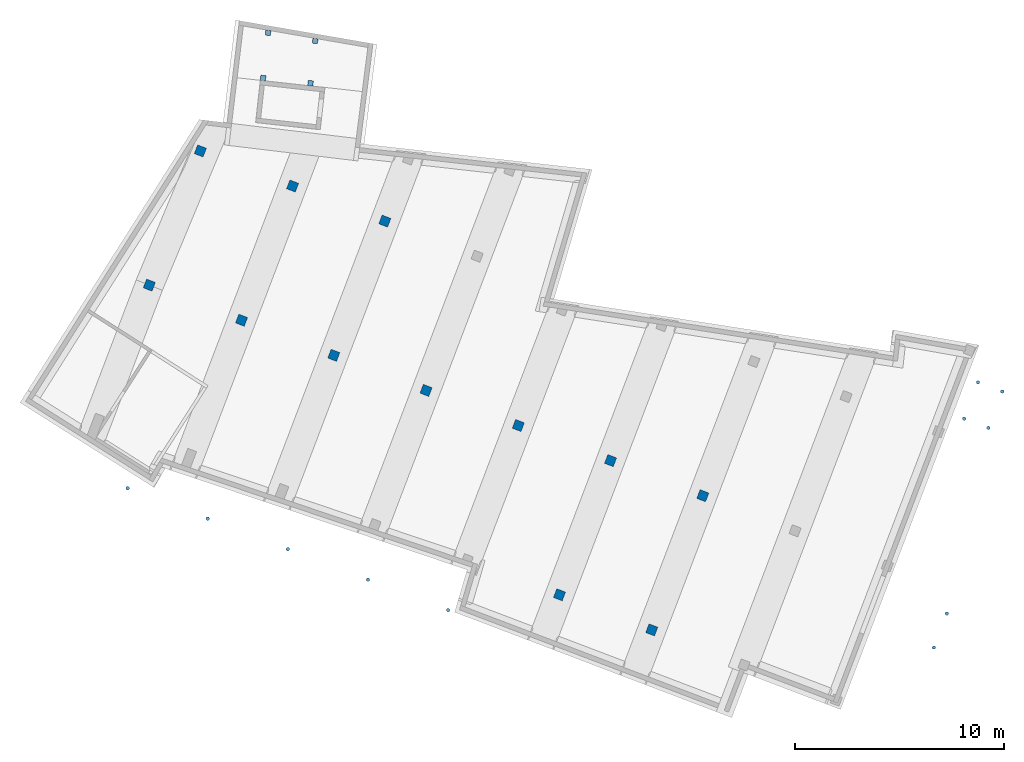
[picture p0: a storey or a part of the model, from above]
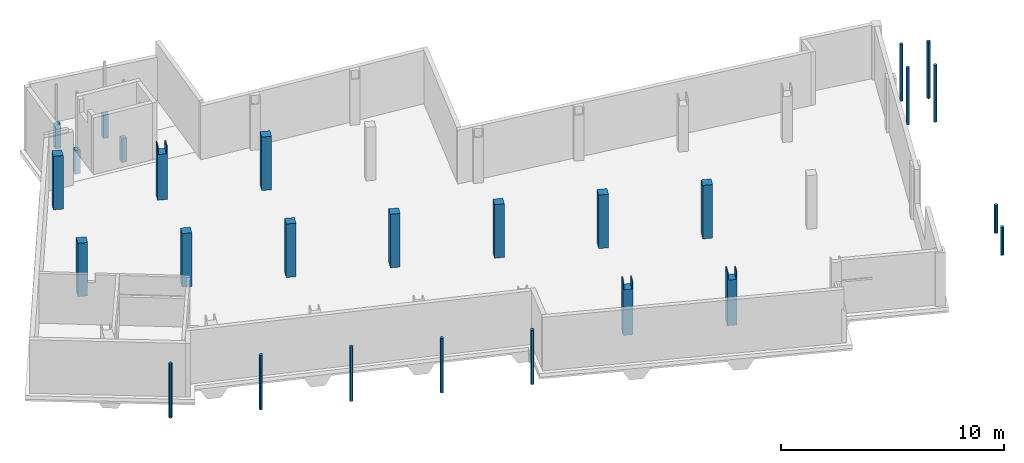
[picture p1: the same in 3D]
Properties of the parts of a building model (IFC2X3), part 1 of 2

# File
Description: ViewDefinition [CoordinationView_V2.0], RevitIdentifiers [ContentGUID: 927a8718-9710-482a-8176-cb94ff4aeceb, VersionGUID: 7923aa44-3987-499f-b0c4-6eacce3661d6, NumberOfSaves: 91], CoordinateReference [CoordinateBase: Shared Coordinates, ProjectSite: Internal], ExchangeRequirement [Structural]
File name: Haarlem - Kruisstraat 30-32_CON_EPA_R25.ifc
Time: 2025-02-14T07:08:31+01:00
Written by: ODA SDAI 24.12
Made in: Autodesk Revit 25.4.0.32 (ENU) - IFC 25.4.0.27

# IfcProject
LongName: Haarlem, Kruisstraat 30-32; Phase: Definitief Ontwerp

# IfcSite, Default
RefLatitude: 42, 24, 53, 508911; RefLongitude: -71, -15, -29, -58837; RefElevation: 0 mm

# IfcBuilding
Pset_BuildingCommon - NumberOfStoreys: 3

# IfcBuildingStorey: Level:Level (3)
Pset_AirSideSystemInformation - sets with these values: 2
Name | LongName = Name | Elevation (mm) | EntranceLevel
-1 kelder | -1 kelder | -3160 | yes
00 begane grond | 00 begane grond | 0 | yes
01 eerste verdieping | 01 eerste verdieping | 4250 | no

# IfcBeam: 130x200mm (11)
In: 00 begane grond
Type - Description: nok 130x200mm; PredefinedType: BEAM
Type - Pset_BeamCommon - LoadBearing: yes
Type - Pset_ConcreteElementGeneral - StructuralClass: -; EnvironmentalClass: -
Type - Pset_FireRatingProperties - FireResistanceRating: -
Type - Pset_ReinforcementBarPitchOfBeam - Description: nok 130x200mm
Classification: 16.12 funderingsconstructies; voeten en balken, fundatie balken (NL-Sfb); Material: beton_gewapend_ihw
Pset_BeamCommon - Slope: 0 deg; IsExternal: no; Reference: nok 130x200mm
Pset_QuantityTakeOff - Reference: nok 130x200mm; sets with these values: 2
ILS Ontwerp en Engineering - 4.3 Dragend: yes; 3.3 Bouwlaag: 00 begane grond; 3.5 Naamgeving element: 16.12_Beton balk; 3.5 Type: nok 130x200mm; 3.6 NL-SfB omschrijving: funderingsconstructies; voeten en balken, fundatie balken; 4.5 C Brandwerendheid hoofddraagconstructie: -; 4.7 Materiaal: beton_gewapend_ihw; 4.8 Bouwfase: Bestaand; 4.8 C Wapeningshoeveelheid: 75,00 kg/m³
Name | Span (mm)
16.12_Beton balk | 3195
16.12_Beton balk | 2267.02
16.12_Beton balk | 2875
2 x 16.12_Beton balk | 580
3 x 16.12_Beton balk | 710
16.12_Beton balk | 6430
16.12_Beton balk | 916.269
16.12_Beton balk | 655

# IfcBeam: 20mm (2)
In: 00 begane grond
Type - Pset_BeamCommon - LoadBearing: yes
Type - Pset_ReinforcementBarPitchOfBeam - Description: w.v.b. ⌀20 S355
Classification: 28.11 hoofddraagconstructies; kolommen en liggers, kolom-/liggerconstructies (NL-Sfb); Material: metaal_staal_profiel_s355
Pset_BeamCommon - IsExternal: no; Reference: 20mm; Span: 7874.2 mm; Slope: 29.1041 deg
Pset_QuantityTakeOff - Reference: 20mm; sets with these values: 2
ILS Ontwerp en Engineering - 4.3 Dragend: yes; 3.3 Bouwlaag: 00 begane grond; 4.7 Materiaal: metaal_staal_profiel_s355; 4.8 Bouwfase: Nieuw
Name (28.11_SF_WVB-StaafRond:20mm:...)
837259
837310

# IfcBeam: 300x300mm, 16.12_Beton balk
In: 00 begane grond
Type - Description: balk 300x600mm; PredefinedType: BEAM; Classification: 16.12 funderingsconstructies; voeten en balken, fundatie balken (NL-Sfb); Material: beton_gewapend_ihw
Type - Pset_BeamCommon - LoadBearing: yes
Type - Pset_ConcreteElementGeneral - StructuralClass: C30/37; EnvironmentalClass: XC3
Type - Pset_FireRatingProperties - FireResistanceRating: -
Type - Pset_ReinforcementBarPitchOfBeam - Description: balk 300x600mm
Pset_BeamCommon - Slope: 0 deg; IsExternal: no; Reference: balk 300x600mm; Span: 14040 mm
Pset_QuantityTakeOff - Reference: balk 300x600mm; sets with these values: 2
ILS Ontwerp en Engineering - 4.3 Dragend: yes; 3.3 Bouwlaag: 00 begane grond; 3.5 Naamgeving element: 16.12_Beton balk; 3.5 Type: balk 300x600mm; 3.6 NL-SfB omschrijving: funderingsconstructies; voeten en balken, fundatie balken; 4.5 C Brandwerendheid hoofddraagconstructie: -; 4.7 Materiaal: beton_gewapend_ihw; 4.8 Bouwfase: Bestaand; 4.8 C Wapeningshoeveelheid: 75,00 kg/m³

# IfcBeam: 300x300mm, 16.12_Beton balk
In: 00 begane grond
Type - Description: balk 300x600mm; PredefinedType: BEAM
Type - Pset_BeamCommon - LoadBearing: yes
Type - Pset_ConcreteElementGeneral - StructuralClass: C30/37; EnvironmentalClass: XC3
Type - Pset_FireRatingProperties - FireResistanceRating: -
Type - Pset_ReinforcementBarPitchOfBeam - Description: balk 300x600mm
Classification: 16.12 funderingsconstructies; voeten en balken, fundatie balken (NL-Sfb); Material: beton_gewapend_ihw
Pset_BeamCommon - Slope: 0 deg; IsExternal: no; Reference: balk 300x600mm; Span: 4451.6 mm
Pset_QuantityTakeOff - Reference: balk 300x600mm; sets with these values: 2
ILS Ontwerp en Engineering - 4.3 Dragend: yes; 3.3 Bouwlaag: 00 begane grond; 3.5 Naamgeving element: 16.12_Beton balk; 3.5 Type: balk 300x600mm; 3.6 NL-SfB omschrijving: funderingsconstructies; voeten en balken, fundatie balken; 4.5 C Brandwerendheid hoofddraagconstructie: -; 4.7 Materiaal: beton_gewapend_ihw; 4.8 Bouwfase: Bestaand; 4.8 C Wapeningshoeveelheid: 75,00 kg/m³

# IfcBeam: 300x400mm (2)
In: 00 begane grond
Type - Description: balk 300x400mm; PredefinedType: BEAM
Type - Pset_BeamCommon - LoadBearing: yes
Type - Pset_ConcreteElementGeneral - StructuralClass: C30/37; EnvironmentalClass: XC3
Type - Pset_FireRatingProperties - FireResistanceRating: -
Type - Pset_ReinforcementBarPitchOfBeam - Description: balk 300x400mm
Classification: 16.12 funderingsconstructies; voeten en balken, fundatie balken (NL-Sfb); Material: beton_gewapend_ihw_c30/37
Pset_BeamCommon - Slope: 0 deg; IsExternal: no; Reference: balk 300x400mm
Pset_QuantityTakeOff - Reference: balk 300x400mm; sets with these values: 2
ILS Ontwerp en Engineering - 4.3 Dragend: yes; 3.3 Bouwlaag: 00 begane grond; 3.5 Naamgeving element: 16.12_Beton balk; 3.5 Type: balk 300x400mm; 3.6 NL-SfB omschrijving: funderingsconstructies; voeten en balken, fundatie balken; 4.5 C Brandwerendheid hoofddraagconstructie: -; 4.7 Materiaal: beton_gewapend_ihw_c30/37; 4.8 Bouwfase: Nieuw; 4.8 C Wapeningshoeveelheid: 75,00 kg/m³
Name | Span (mm)
16.12_Beton balk | 17103.8
16.12_Beton balk | 1206.15

# IfcBeam: 300x400mm (3)
In: 00 begane grond
Type - Description: balk 450x300; PredefinedType: BEAM
Type - Pset_BeamCommon - LoadBearing: yes
Type - Pset_ConcreteElementGeneral - StructuralClass: C30/37; EnvironmentalClass: XC3
Type - Pset_FireRatingProperties - FireResistanceRating: -
Type - Pset_ReinforcementBarPitchOfBeam - Description: balk 450x300
Classification: 16.12 funderingsconstructies; voeten en balken, fundatie balken (NL-Sfb); Material: beton_gewapend_ihw
Pset_BeamCommon - Slope: 0 deg; IsExternal: no; Reference: balk 450x300mm
Pset_QuantityTakeOff - Reference: balk 450x300mm; sets with these values: 2
ILS Ontwerp en Engineering - 4.3 Dragend: yes; 3.3 Bouwlaag: 00 begane grond; 3.5 Naamgeving element: 16.12_Beton balk; 3.5 Type: balk 450x300; 3.6 NL-SfB omschrijving: funderingsconstructies; voeten en balken, fundatie balken; 4.5 C Brandwerendheid hoofddraagconstructie: -; 4.7 Materiaal: beton_gewapend_ihw; 4.8 Bouwfase: Nieuw; 4.8 C Wapeningshoeveelheid: 75,00 kg/m³
Name | Span (mm)
2 x 16.12_Beton balk | 1780
16.12_Beton balk | 1550

# IfcBeam: 650x600mm (11)
In: -1 kelder
Type - Description: versterktestrook; PredefinedType: BEAM; Classification: 16.12 funderingsconstructies; voeten en balken, fundatie balken (NL-Sfb); Material: beton_gewapend_ihw
Type - Pset_BeamCommon - LoadBearing: yes
Type - Pset_ConcreteElementGeneral - StructuralClass: -; EnvironmentalClass: -
Type - Pset_FireRatingProperties - FireResistanceRating: -
Type - Pset_ReinforcementBarPitchOfBeam - Description: versterktestrook
Pset_BeamCommon - Slope: 0 deg; IsExternal: no; Reference: 600x300
Pset_QuantityTakeOff - Reference: 600x300; sets with these values: 2
ILS Ontwerp en Engineering - 4.3 Dragend: yes; 3.3 Bouwlaag: Level : -1 kelder; 3.5 Naamgeving element: 16.12_Beton balk; 3.5 Type: versterktestrook; 3.6 NL-SfB omschrijving: funderingsconstructies; voeten en balken, fundatie balken; 4.5 C Brandwerendheid hoofddraagconstructie: -; 4.7 Materiaal: beton_gewapend_ihw; 4.8 Bouwfase: Bestaand; 4.8 C Wapeningshoeveelheid: 75,00 kg/m³
Name | Span (mm)
16.12_Beton balk | 14210.1
16.12_Beton balk | 2119.67
16.12_Beton balk | 15561.7
16.12_Beton balk | 7614.8
16.12_Beton balk | 1367.46
16.12_Beton balk | 16197.5
16.12_Beton balk | 11143.6
16.12_Beton balk | 6475.45
16.12_Beton balk | 17140
16.12_Beton balk | 4163.4
16.12_Beton balk | 1045.66

# IfcBeam: 650x600mm (17)
Type - Description: versterktestrook; PredefinedType: BEAM
Type - Pset_BeamCommon - LoadBearing: yes
Type - Pset_ConcreteElementGeneral - StructuralClass: -; EnvironmentalClass: -
Type - Pset_FireRatingProperties - FireResistanceRating: -
Type - Pset_ReinforcementBarPitchOfBeam - Description: versterktestrook
Classification: 16.12 funderingsconstructies; voeten en balken, fundatie balken (NL-Sfb); Material: beton_gewapend_ihw
Pset_BeamCommon - Slope: 0 deg; IsExternal: no
Pset_QuantityTakeOff - sets with these values: 2
ILS Ontwerp en Engineering - 4.3 Dragend: yes; 3.5 Naamgeving element: 16.12_Beton balk; 3.5 Type: versterktestrook; 3.6 NL-SfB omschrijving: funderingsconstructies; voeten en balken, fundatie balken; 4.5 C Brandwerendheid hoofddraagconstructie: -; 4.7 Materiaal: beton_gewapend_ihw; 4.8 Bouwfase: Bestaand; 4.8 C Wapeningshoeveelheid: 75,00 kg/m³
Name | In | Pset_BeamCommon, Reference = Pset_QuantityTakeOff, Reference | Span (mm) | 3.3 Bouwlaag
16.12_Beton balk | -1 kelder | 650x600mm | 19480 | -1 kelder
16.12_Beton balk | -1 kelder | 650x600mm | 18460 | -1 kelder
16.12_Beton balk | -1 kelder | 650x600mm | 17031.7 | -1 kelder
16.12_Beton balk | -1 kelder | 650x600mm | 8140 | -1 kelder
16.12_Beton balk | -1 kelder | 650x600mm | 8660 | -1 kelder
16.12_Beton balk | -1 kelder | 650x600mm | 13880 | -1 kelder
16.12_Beton balk | -1 kelder | 650x600mm | 16960 | -1 kelder
16.12_Beton balk | -1 kelder | 650x600mm | 17920 | -1 kelder
16.12_Beton balk | -1 kelder | 650x600mm | 16660 | -1 kelder
16.12_Beton balk | -1 kelder | 700x300 | 18685.9 | -1 kelder
16.12_Beton balk | -1 kelder | 700x300 | 4730 | Level : -1 kelder
16.12_Beton balk | -1 kelder | 700x300 | 2217.02 | Level : -1 kelder
16.12_Beton balk | 00 begane grond | 950x1170mm | 12633.1 | 00 begane grond
16.12_Beton balk | 00 begane grond | 950x1170mm | 738.395 | 00 begane grond
16.12_Beton balk | 00 begane grond | 950x1170mm | 7010.68 | 00 begane grond
16.12_Beton balk | 00 begane grond | 950x1170mm | 6925.56 | 00 begane grond
16.12_Beton balk | 00 begane grond | 950x1170mm | 6964.59 | 00 begane grond

# IfcBeam: DIE10 (22)
In: 01 eerste verdieping
Type - Description: DIE10; PredefinedType: BEAM
Type - Pset_BeamCommon - LoadBearing: yes
Type - Pset_ConcreteElementGeneral - StructuralClass: S235; EnvironmentalClass: -
Type - Pset_FireRatingProperties - FireResistanceRating: 90
Type - Pset_ReinforcementBarPitchOfBeam - Description: DIE10
Classification: 28.11 hoofddraagconstructies; kolommen en liggers, kolom-/liggerconstructies (NL-Sfb); Material: metaal_staal_generiek
Pset_BeamCommon - Slope: 0 deg; IsExternal: no; Reference: DIE10
Pset_QuantityTakeOff - Reference: DIE10; sets with these values: 2
ILS Ontwerp en Engineering - 4.3 Dragend: yes; 3.3 Bouwlaag: 01 eerste verdieping; 3.5 Naamgeving element: 28.11_Stalen balk HEA; 3.5 Type: DIE10; 3.6 NL-SfB omschrijving: hoofddraagconstructies; kolommen en liggers, kolom-/liggerconstructies; 4.5 C Brandwerendheid hoofddraagconstructie: 90; 4.7 Materiaal: metaal_staal_generiek; 4.8 Bouwfase: Bestaand; 4.8 C Sterkteklasse: S235; 4.8 C Milieuklasse: -
Name | Span (mm)
20 x 28.11_Stalen balk HEA | 4730
28.11_Stalen balk HEA | 1205
28.11_Stalen balk HEA | 2179.8

# IfcBeam: DIE16 (2)
In: 01 eerste verdieping
Type - Description: DIE16; PredefinedType: BEAM
Type - Pset_BeamCommon - LoadBearing: yes
Type - Pset_ConcreteElementGeneral - StructuralClass: S235; EnvironmentalClass: -
Type - Pset_FireRatingProperties - FireResistanceRating: 90
Type - Pset_ReinforcementBarPitchOfBeam - Description: DIE16
Classification: 28.11 hoofddraagconstructies; kolommen en liggers, kolom-/liggerconstructies (NL-Sfb); Material: metaal_staal_generiek
Pset_BeamCommon - Slope: 0 deg; IsExternal: no; Reference: DIE16
Pset_QuantityTakeOff - Reference: DIE16; sets with these values: 2
ILS Ontwerp en Engineering - 4.3 Dragend: yes; 3.3 Bouwlaag: 01 eerste verdieping; 3.5 Naamgeving element: 28.11_Stalen balk HEA; 3.5 Type: DIE16; 3.6 NL-SfB omschrijving: hoofddraagconstructies; kolommen en liggers, kolom-/liggerconstructies; 4.5 C Brandwerendheid hoofddraagconstructie: 90; 4.7 Materiaal: metaal_staal_generiek; 4.8 Bouwfase: Bestaand; 4.8 C Sterkteklasse: S235; 4.8 C Milieuklasse: -
Name | Span (mm)
28.11_Stalen balk HEA | 1736.7
28.11_Stalen balk HEA | 4780.1

# IfcBeam: DIE18 (4)
In: 01 eerste verdieping
Type - Description: DIE18; PredefinedType: BEAM
Type - Pset_BeamCommon - LoadBearing: yes
Type - Pset_ConcreteElementGeneral - StructuralClass: S235; EnvironmentalClass: -
Type - Pset_FireRatingProperties - FireResistanceRating: 90
Type - Pset_ReinforcementBarPitchOfBeam - Description: DIE18
Classification: 28.11 hoofddraagconstructies; kolommen en liggers, kolom-/liggerconstructies (NL-Sfb); Material: metaal_staal_generiek
Pset_BeamCommon - Slope: 0 deg; IsExternal: no; Reference: DIE18
Pset_QuantityTakeOff - Reference: DIE18; sets with these values: 2
ILS Ontwerp en Engineering - 4.3 Dragend: yes; 3.3 Bouwlaag: 01 eerste verdieping; 3.5 Naamgeving element: 28.11_Stalen balk HEA; 3.5 Type: DIE18; 3.6 NL-SfB omschrijving: hoofddraagconstructies; kolommen en liggers, kolom-/liggerconstructies; 4.5 C Brandwerendheid hoofddraagconstructie: 90; 4.7 Materiaal: metaal_staal_generiek; 4.8 Bouwfase: Bestaand; 4.8 C Sterkteklasse: S235; 4.8 C Milieuklasse: -
Name | Span (mm)
2 x 28.11_Stalen balk HEA | 2117
28.11_Stalen balk HEA | 2078
28.11_Stalen balk HEA | 3132

# IfcBeam: DIE20, 28.11_Stalen balk HEA
In: 01 eerste verdieping
Type - Description: DIE20; PredefinedType: BEAM
Type - Pset_BeamCommon - LoadBearing: yes
Type - Pset_ConcreteElementGeneral - StructuralClass: S235; EnvironmentalClass: -
Type - Pset_FireRatingProperties - FireResistanceRating: 90
Type - Pset_ReinforcementBarPitchOfBeam - Description: DIE20
Classification: 28.11 hoofddraagconstructies; kolommen en liggers, kolom-/liggerconstructies (NL-Sfb); Material: metaal_staal_generiek
Pset_BeamCommon - Slope: 0 deg; IsExternal: no; Reference: DIE20; Span: 2117 mm
Pset_QuantityTakeOff - Reference: DIE20; sets with these values: 2
ILS Ontwerp en Engineering - 4.3 Dragend: yes; 3.3 Bouwlaag: 01 eerste verdieping; 3.5 Naamgeving element: 28.11_Stalen balk HEA; 3.5 Type: DIE20; 3.6 NL-SfB omschrijving: hoofddraagconstructies; kolommen en liggers, kolom-/liggerconstructies; 4.5 C Brandwerendheid hoofddraagconstructie: 90; 4.7 Materiaal: metaal_staal_generiek; 4.8 Bouwfase: Bestaand; 4.8 C Sterkteklasse: S235; 4.8 C Milieuklasse: -

# IfcBeam: DIE22, 28.11_Stalen balk HEA
In: 01 eerste verdieping
Type - Description: DIE22; PredefinedType: BEAM
Type - Pset_BeamCommon - LoadBearing: yes
Type - Pset_ConcreteElementGeneral - StructuralClass: S235; EnvironmentalClass: -
Type - Pset_FireRatingProperties - FireResistanceRating: 90
Type - Pset_ReinforcementBarPitchOfBeam - Description: DIE22
Classification: 28.11 hoofddraagconstructies; kolommen en liggers, kolom-/liggerconstructies (NL-Sfb); Material: metaal_staal_generiek
Pset_BeamCommon - Slope: 0 deg; IsExternal: no; Reference: DIE22; Span: 3227.6 mm
Pset_QuantityTakeOff - Reference: DIE22; sets with these values: 2
ILS Ontwerp en Engineering - 4.3 Dragend: yes; 3.3 Bouwlaag: 01 eerste verdieping; 3.5 Naamgeving element: 28.11_Stalen balk HEA; 3.5 Type: DIE22; 3.6 NL-SfB omschrijving: hoofddraagconstructies; kolommen en liggers, kolom-/liggerconstructies; 4.5 C Brandwerendheid hoofddraagconstructie: 90; 4.7 Materiaal: metaal_staal_generiek; 4.8 Bouwfase: Bestaand; 4.8 C Sterkteklasse: S235; 4.8 C Milieuklasse: -

# IfcBeam: DIE24 (2)
In: 01 eerste verdieping
Type - Description: DIE24; PredefinedType: BEAM
Type - Pset_BeamCommon - LoadBearing: yes
Type - Pset_ConcreteElementGeneral - StructuralClass: S235; EnvironmentalClass: -
Type - Pset_FireRatingProperties - FireResistanceRating: 90
Type - Pset_ReinforcementBarPitchOfBeam - Description: DIE24
Classification: 28.11 hoofddraagconstructies; kolommen en liggers, kolom-/liggerconstructies (NL-Sfb); Material: metaal_staal_generiek
Pset_BeamCommon - Slope: 0 deg; IsExternal: no; Span: 4730 mm; Reference: DIE24
Pset_QuantityTakeOff - Reference: DIE24; sets with these values: 2
ILS Ontwerp en Engineering - 4.3 Dragend: yes; 3.3 Bouwlaag: 01 eerste verdieping; 3.5 Naamgeving element: 28.11_Stalen balk HEA; 3.5 Type: DIE24; 3.6 NL-SfB omschrijving: hoofddraagconstructies; kolommen en liggers, kolom-/liggerconstructies; 4.5 C Brandwerendheid hoofddraagconstructie: 90; 4.7 Materiaal: metaal_staal_generiek; 4.8 Bouwfase: Bestaand; 4.8 C Sterkteklasse: S235; 4.8 C Milieuklasse: -

# IfcBeam: DIE26 (10)
In: 01 eerste verdieping
Type - Description: DIE26; PredefinedType: BEAM
Type - Pset_BeamCommon - LoadBearing: yes
Type - Pset_ConcreteElementGeneral - StructuralClass: S235; EnvironmentalClass: -
Type - Pset_FireRatingProperties - FireResistanceRating: 90
Type - Pset_ReinforcementBarPitchOfBeam - Description: DIE26
Classification: 28.11 hoofddraagconstructies; kolommen en liggers, kolom-/liggerconstructies (NL-Sfb); Material: metaal_staal_generiek
Pset_BeamCommon - Slope: 0 deg; IsExternal: no; Reference: DIE26
Pset_QuantityTakeOff - Reference: DIE26; sets with these values: 2
ILS Ontwerp en Engineering - 4.3 Dragend: yes; 3.3 Bouwlaag: 01 eerste verdieping; 3.5 Naamgeving element: 28.11_Stalen balk HEA; 3.5 Type: DIE26; 3.6 NL-SfB omschrijving: hoofddraagconstructies; kolommen en liggers, kolom-/liggerconstructies; 4.5 C Brandwerendheid hoofddraagconstructie: 90; 4.7 Materiaal: metaal_staal_generiek; 4.8 Bouwfase: Bestaand; 4.8 C Sterkteklasse: S235; 4.8 C Milieuklasse: -
Name | Span (mm)
28.11_Stalen balk HEA | 4730
28.11_Stalen balk HEA | 4479.3
28.11_Stalen balk HEA | 4317
28.11_Stalen balk HEA | 4449.2
28.11_Stalen balk HEA | 6880
28.11_Stalen balk HEA | 6789
28.11_Stalen balk HEA | 1799.2
28.11_Stalen balk HEA | 5010.3
28.11_Stalen balk HEA | 6900
28.11_Stalen balk HEA | 4220

# IfcBeam: DIE28 (2)
In: 01 eerste verdieping
Type - Description: DIE28; PredefinedType: BEAM
Type - Pset_BeamCommon - LoadBearing: yes
Type - Pset_ConcreteElementGeneral - StructuralClass: S235; EnvironmentalClass: -
Type - Pset_FireRatingProperties - FireResistanceRating: 90
Type - Pset_ReinforcementBarPitchOfBeam - Description: DIE28
Classification: 28.11 hoofddraagconstructies; kolommen en liggers, kolom-/liggerconstructies (NL-Sfb); Material: metaal_staal_generiek
Pset_BeamCommon - Slope: 0 deg; IsExternal: no; Reference: DIE28
Pset_QuantityTakeOff - Reference: DIE28; sets with these values: 2
ILS Ontwerp en Engineering - 4.3 Dragend: yes; 3.3 Bouwlaag: 01 eerste verdieping; 3.5 Naamgeving element: 28.11_Stalen balk HEA; 3.5 Type: DIE28; 3.6 NL-SfB omschrijving: hoofddraagconstructies; kolommen en liggers, kolom-/liggerconstructies; 4.5 C Brandwerendheid hoofddraagconstructie: 90; 4.7 Materiaal: metaal_staal_generiek; 4.8 Bouwfase: Bestaand; 4.8 C Sterkteklasse: S235; 4.8 C Milieuklasse: -
Name | Span (mm)
28.11_Stalen balk HEA | 4730.1
28.11_Stalen balk HEA | 4203.6

# IfcBeam: DIE32, 28.11_Stalen balk HEA
In: 01 eerste verdieping
Type - Description: DIE32; PredefinedType: BEAM
Type - Pset_BeamCommon - LoadBearing: yes
Type - Pset_ConcreteElementGeneral - StructuralClass: S235; EnvironmentalClass: -
Type - Pset_FireRatingProperties - FireResistanceRating: 90
Type - Pset_ReinforcementBarPitchOfBeam - Description: DIE32
Classification: 28.11 hoofddraagconstructies; kolommen en liggers, kolom-/liggerconstructies (NL-Sfb); Material: metaal_staal_generiek
Pset_BeamCommon - Slope: 0 deg; IsExternal: no; Reference: DIE32; Span: 5066.4 mm
Pset_QuantityTakeOff - Reference: DIE32; sets with these values: 2
ILS Ontwerp en Engineering - 4.3 Dragend: yes; 3.3 Bouwlaag: 01 eerste verdieping; 3.5 Naamgeving element: 28.11_Stalen balk HEA; 3.5 Type: DIE32; 3.6 NL-SfB omschrijving: hoofddraagconstructies; kolommen en liggers, kolom-/liggerconstructies; 4.5 C Brandwerendheid hoofddraagconstructie: 90; 4.7 Materiaal: metaal_staal_generiek; 4.8 Bouwfase: Bestaand; 4.8 C Sterkteklasse: S235; 4.8 C Milieuklasse: -

# IfcBeam: DIE34, 28.11_Stalen balk HEA
In: 01 eerste verdieping
Type - Description: DIE34; PredefinedType: BEAM
Type - Pset_BeamCommon - LoadBearing: yes
Type - Pset_ConcreteElementGeneral - StructuralClass: S235; EnvironmentalClass: -
Type - Pset_FireRatingProperties - FireResistanceRating: 90
Type - Pset_ReinforcementBarPitchOfBeam - Description: DIE34
Classification: 28.11 hoofddraagconstructies; kolommen en liggers, kolom-/liggerconstructies (NL-Sfb); Material: metaal_staal_generiek
Pset_BeamCommon - Slope: 0 deg; IsExternal: no; Reference: DIE34; Span: 5970 mm
Pset_QuantityTakeOff - Reference: DIE34; sets with these values: 2
ILS Ontwerp en Engineering - 4.3 Dragend: yes; 3.3 Bouwlaag: 01 eerste verdieping; 3.5 Naamgeving element: 28.11_Stalen balk HEA; 3.5 Type: DIE34; 3.6 NL-SfB omschrijving: hoofddraagconstructies; kolommen en liggers, kolom-/liggerconstructies; 4.5 C Brandwerendheid hoofddraagconstructie: 90; 4.7 Materiaal: metaal_staal_generiek; 4.8 Bouwfase: Bestaand; 4.8 C Sterkteklasse: S235; 4.8 C Milieuklasse: -

# IfcBeam: DIE38 (11)
In: 01 eerste verdieping
Type - Description: DIE38; PredefinedType: BEAM
Type - Pset_BeamCommon - LoadBearing: yes
Type - Pset_ConcreteElementGeneral - StructuralClass: S235; EnvironmentalClass: -
Type - Pset_FireRatingProperties - FireResistanceRating: 90
Type - Pset_ReinforcementBarPitchOfBeam - Description: DIE38
Classification: 28.11 hoofddraagconstructies; kolommen en liggers, kolom-/liggerconstructies (NL-Sfb); Material: metaal_staal_generiek
Pset_BeamCommon - Slope: 0 deg; IsExternal: no; Reference: DIE38
Pset_QuantityTakeOff - Reference: DIE38; sets with these values: 2
ILS Ontwerp en Engineering - 4.3 Dragend: yes; 3.3 Bouwlaag: 01 eerste verdieping; 3.5 Naamgeving element: 28.11_Stalen balk HEA; 3.5 Type: DIE38; 3.6 NL-SfB omschrijving: hoofddraagconstructies; kolommen en liggers, kolom-/liggerconstructies; 4.5 C Brandwerendheid hoofddraagconstructie: 90; 4.7 Materiaal: metaal_staal_generiek; 4.8 Bouwfase: Bestaand; 4.8 C Sterkteklasse: S235; 4.8 C Milieuklasse: -
Name | Span (mm)
28.11_Stalen balk HEA | 265
4 x 28.11_Stalen balk HEA | 13760
28.11_Stalen balk HEA | 12859.2
28.11_Stalen balk HEA | 14027.2
28.11_Stalen balk HEA | 14169.1
28.11_Stalen balk HEA | 14356.4
28.11_Stalen balk HEA | 14647.7
28.11_Stalen balk HEA | 7005

# IfcBeam: HEA140 (3)
In: 00 begane grond
Type - Description: HEA140; PredefinedType: BEAM
Type - Pset_BeamCommon - LoadBearing: yes
Type - Pset_ConcreteElementGeneral - StructuralClass: S235; EnvironmentalClass: -
Type - Pset_FireRatingProperties - FireResistanceRating: 90
Type - Pset_ReinforcementBarPitchOfBeam - Description: HEA140
Classification: 28.11 hoofddraagconstructies; kolommen en liggers, kolom-/liggerconstructies (NL-Sfb); Material: metaal_staal_generiek
Pset_BeamCommon - IsExternal: no; Reference: HEA140
Pset_QuantityTakeOff - Reference: HEA140; sets with these values: 2
ILS Ontwerp en Engineering - 4.3 Dragend: yes; 3.3 Bouwlaag: 00 begane grond; 3.5 Naamgeving element: 28.11_Stalen balk HEA; 3.5 Type: HEA140; 3.6 NL-SfB omschrijving: hoofddraagconstructies; kolommen en liggers, kolom-/liggerconstructies; 4.5 C Brandwerendheid hoofddraagconstructie: 90; 4.7 Materiaal: metaal_staal_generiek; 4.8 Bouwfase: Nieuw; 4.8 C Sterkteklasse: S235; 4.8 C Milieuklasse: -
Name | Slope (deg) | Span (mm)
28.11_Stalen balk HEA | 0 | 2140
28.11_Stalen balk HEA | 0 | 2280.5
28.11_Stalen balk HEA | 16.9275 | 2404.2

# IfcBeam: HEA160 (16)
Type - Description: HEA160; PredefinedType: BEAM
Type - Pset_BeamCommon - LoadBearing: yes
Type - Pset_ConcreteElementGeneral - StructuralClass: S235; EnvironmentalClass: -
Type - Pset_FireRatingProperties - FireResistanceRating: 90
Type - Pset_ReinforcementBarPitchOfBeam - Description: HEA160
Classification: 28.11 hoofddraagconstructies; kolommen en liggers, kolom-/liggerconstructies (NL-Sfb)
Pset_BeamCommon - Slope: 0 deg; IsExternal: no; Reference: HEA160
Pset_QuantityTakeOff - Reference: HEA160; sets with these values: 2
ILS Ontwerp en Engineering - 4.3 Dragend: yes; 3.5 Naamgeving element: 28.11_Stalen balk HEA; 3.5 Type: HEA160; 3.6 NL-SfB omschrijving: hoofddraagconstructies; kolommen en liggers, kolom-/liggerconstructies; 4.5 C Brandwerendheid hoofddraagconstructie: 90; 4.8 Bouwfase: Nieuw; 4.8 C Sterkteklasse: S235; 4.8 C Milieuklasse: -
Name | In | Material = 4.7 Materiaal | Span (mm) | 3.3 Bouwlaag
28.11_Stalen balk HEA | 01 eerste verdieping | metaal_staal_profiel_s235 | 4730 | 01 eerste verdieping
28.11_Stalen balk HEA | 01 eerste verdieping | metaal_staal_profiel_s235 | 4835.6 | 01 eerste verdieping
28.11_Stalen balk HEA | 01 eerste verdieping | metaal_staal_profiel_s235 | 1706.7 | 01 eerste verdieping
28.11_Stalen balk HEA | 00 begane grond | metaal_staal_generiek | 5417.6 | 00 begane grond
28.11_Stalen balk HEA | 00 begane grond | metaal_staal_generiek | 904.8 | 00 begane grond
28.11_Stalen balk HEA | 00 begane grond | metaal_staal_generiek | 422.7 | 00 begane grond
2 x 28.11_Stalen balk HEA | 01 eerste verdieping | metaal_staal_profiel_s235 | 4835.7 | 01 eerste verdieping
2 x 28.11_Stalen balk HEA | 01 eerste verdieping | metaal_staal_profiel_s235 | 3550 | 01 eerste verdieping
5 x 28.11_Stalen balk HEA | 01 eerste verdieping | metaal_staal_profiel_s235 | 3700 | 01 eerste verdieping
28.11_Stalen balk HEA | 01 eerste verdieping | metaal_staal_profiel_s235 | 2447 | 01 eerste verdieping

# IfcBeam: HEA180 (15)
In: 01 eerste verdieping
Type - Description: HEA180; PredefinedType: BEAM
Type - Pset_BeamCommon - LoadBearing: yes
Type - Pset_ConcreteElementGeneral - StructuralClass: S235; EnvironmentalClass: -
Type - Pset_FireRatingProperties - FireResistanceRating: 90
Type - Pset_ReinforcementBarPitchOfBeam - Description: HEA180
Classification: 28.11 hoofddraagconstructies; kolommen en liggers, kolom-/liggerconstructies (NL-Sfb)
Pset_BeamCommon - IsExternal: no; Reference: HEA180
Pset_QuantityTakeOff - Reference: HEA180; sets with these values: 2
ILS Ontwerp en Engineering - 4.3 Dragend: yes; 3.3 Bouwlaag: 01 eerste verdieping; 3.5 Naamgeving element: 28.11_Stalen balk HEA; 3.5 Type: HEA180; 3.6 NL-SfB omschrijving: hoofddraagconstructies; kolommen en liggers, kolom-/liggerconstructies; 4.5 C Brandwerendheid hoofddraagconstructie: 90; 4.8 Bouwfase: Nieuw; 4.8 C Sterkteklasse: S235; 4.8 C Milieuklasse: -
Name | Material = 4.7 Materiaal | Slope (deg) | Span (mm)
28.11_Stalen balk HEA | metaal_staal_profiel_s235 | 0 | 3550
2 x 28.11_Stalen balk HEA | metaal_staal_profiel_s235 | 0 | 4730
28.11_Stalen balk HEA | metaal_staal_generiek | 0.000338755 | 4730
28.11_Stalen balk HEA | metaal_staal_generiek | 0.000338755 | 2356.7
2 x 28.11_Stalen balk HEA | metaal_staal_generiek | 0 | 4730
28.11_Stalen balk HEA | metaal_staal_generiek | 0 | 2330
28.11_Stalen balk HEA | metaal_staal_generiek | 0 | 3272.8
28.11_Stalen balk HEA | metaal_staal_generiek | 0 | 4729.9
28.11_Stalen balk HEA | metaal_staal_generiek | 0 | 1620
28.11_Stalen balk HEA | metaal_staal_profiel_s235 | 0 | 2330
28.11_Stalen balk HEA | metaal_staal_profiel_s235 | 0 | 3188.5
28.11_Stalen balk HEA | metaal_staal_profiel_s235 | 0 | 2234.8
28.11_Stalen balk HEA | metaal_staal_profiel_s235 | 0 | 1234.9

# IfcBeam: HEA200 (13)
Type - Description: HEA200; PredefinedType: BEAM
Type - Pset_BeamCommon - LoadBearing: yes
Type - Pset_ConcreteElementGeneral - StructuralClass: S235; EnvironmentalClass: -
Type - Pset_FireRatingProperties - FireResistanceRating: 90
Type - Pset_ReinforcementBarPitchOfBeam - Description: HEA200
Classification: 28.11 hoofddraagconstructies; kolommen en liggers, kolom-/liggerconstructies (NL-Sfb); Material: metaal_staal_profiel_s235
Pset_BeamCommon - Slope: 0 deg; IsExternal: no; Reference: HEA200
Pset_QuantityTakeOff - Reference: HEA200; sets with these values: 2
ILS Ontwerp en Engineering - 4.3 Dragend: yes; 3.5 Naamgeving element: 28.11_Stalen balk HEA; 3.5 Type: HEA200; 3.6 NL-SfB omschrijving: hoofddraagconstructies; kolommen en liggers, kolom-/liggerconstructies; 4.5 C Brandwerendheid hoofddraagconstructie: 90; 4.7 Materiaal: metaal_staal_profiel_s235; 4.8 Bouwfase: Nieuw; 4.8 C Sterkteklasse: S235; 4.8 C Milieuklasse: -
Name | In | Span (mm) | 3.3 Bouwlaag
10 x 28.11_Stalen balk HEA | 01 eerste verdieping | 3700 | 01 eerste verdieping
28.11_Stalen balk HEA | 01 eerste verdieping | 3469.4 | 01 eerste verdieping
28.11_Stalen balk HEA | 00 begane grond | 7324.1 | 00 begane grond
28.11_Stalen balk HEA | 01 eerste verdieping | 2088.3 | 01 eerste verdieping

# IfcBeam: HEA220 (6)
Type - Description: HEA220; PredefinedType: BEAM
Type - Pset_BeamCommon - LoadBearing: yes
Type - Pset_ConcreteElementGeneral - StructuralClass: S235; EnvironmentalClass: -
Type - Pset_FireRatingProperties - FireResistanceRating: 90
Type - Pset_ReinforcementBarPitchOfBeam - Description: HEA220
Classification: 28.11 hoofddraagconstructies; kolommen en liggers, kolom-/liggerconstructies (NL-Sfb)
Pset_BeamCommon - Slope: 0 deg; IsExternal: no; Reference: HEA220
Pset_QuantityTakeOff - Reference: HEA220; sets with these values: 2
ILS Ontwerp en Engineering - 4.3 Dragend: yes; 3.5 Naamgeving element: 28.11_Stalen balk HEA; 3.5 Type: HEA220; 3.6 NL-SfB omschrijving: hoofddraagconstructies; kolommen en liggers, kolom-/liggerconstructies; 4.5 C Brandwerendheid hoofddraagconstructie: 90; 4.8 Bouwfase: Nieuw; 4.8 C Sterkteklasse: S235; 4.8 C Milieuklasse: -
Name | In | Material = 4.7 Materiaal | Span (mm) | 3.3 Bouwlaag
28.11_Stalen balk HEA | 00 begane grond | metaal_staal_generiek | 4886.4 | 00 begane grond
2 x 28.11_Stalen balk HEA | 01 eerste verdieping | metaal_staal_profiel_s235 | 3550 | 01 eerste verdieping
2 x 28.11_Stalen balk HEA | 01 eerste verdieping | metaal_staal_profiel_s235 | 1234.9 | 01 eerste verdieping
28.11_Stalen balk HEA | 00 begane grond | metaal_staal_generiek | 4730 | 00 begane grond

# IfcBeam: HEA260 (7)
In: 01 eerste verdieping
Type - Description: HEA260; PredefinedType: BEAM
Type - Pset_BeamCommon - LoadBearing: yes
Type - Pset_ConcreteElementGeneral - StructuralClass: S235; EnvironmentalClass: -
Type - Pset_FireRatingProperties - FireResistanceRating: 90
Type - Pset_ReinforcementBarPitchOfBeam - Description: HEA260
Classification: 28.11 hoofddraagconstructies; kolommen en liggers, kolom-/liggerconstructies (NL-Sfb); Material: metaal_staal_profiel_s235
Pset_BeamCommon - Slope: 0 deg; IsExternal: no; Reference: HEA260
Pset_QuantityTakeOff - Reference: HEA260; sets with these values: 2
ILS Ontwerp en Engineering - 4.3 Dragend: yes; 3.3 Bouwlaag: 01 eerste verdieping; 3.5 Naamgeving element: 28.11_Stalen balk HEA; 3.5 Type: HEA260; 3.6 NL-SfB omschrijving: hoofddraagconstructies; kolommen en liggers, kolom-/liggerconstructies; 4.5 C Brandwerendheid hoofddraagconstructie: 90; 4.7 Materiaal: metaal_staal_profiel_s235; 4.8 Bouwfase: Nieuw; 4.8 C Sterkteklasse: S235; 4.8 C Milieuklasse: -
Name | Span (mm)
28.11_Stalen balk HEA | 5854.5
28.11_Stalen balk HEA | 5671.5
28.11_Stalen balk HEA | 4648.3
28.11_Stalen balk HEA | 3700
28.11_Stalen balk HEA | 6961.4
28.11_Stalen balk HEA | 6427.1
28.11_Stalen balk HEA | 4387.8

# IfcBeam: HEA300 (40)
In: 01 eerste verdieping
Type - Description: HEA300; PredefinedType: BEAM
Type - Pset_BeamCommon - LoadBearing: yes
Type - Pset_ConcreteElementGeneral - StructuralClass: S235; EnvironmentalClass: -
Type - Pset_FireRatingProperties - FireResistanceRating: 90
Type - Pset_ReinforcementBarPitchOfBeam - Description: HEA300
Classification: 28.11 hoofddraagconstructies; kolommen en liggers, kolom-/liggerconstructies (NL-Sfb); Material: metaal_staal_profiel_s235
Pset_BeamCommon - Slope: 0 deg; IsExternal: no; Reference: HEA300
Pset_QuantityTakeOff - Reference: HEA300; sets with these values: 2
ILS Ontwerp en Engineering - 4.3 Dragend: yes; 3.3 Bouwlaag: 01 eerste verdieping; 3.5 Naamgeving element: 28.11_Stalen balk HEA; 3.5 Type: HEA300; 3.6 NL-SfB omschrijving: hoofddraagconstructies; kolommen en liggers, kolom-/liggerconstructies; 4.5 C Brandwerendheid hoofddraagconstructie: 90; 4.7 Materiaal: metaal_staal_profiel_s235; 4.8 Bouwfase: Nieuw; 4.8 C Sterkteklasse: S235; 4.8 C Milieuklasse: -
Name | Span (mm)
2 x 28.11_Stalen balk HEA | 4236.2
24 x 28.11_Stalen balk HEA | 4730
3 x 28.11_Stalen balk HEA | 4479.3
28.11_Stalen balk HEA | 4224.3
4 x 28.11_Stalen balk HEA | 3700
2 x 28.11_Stalen balk HEA | 3550
2 x 28.11_Stalen balk HEA | 4742.4
28.11_Stalen balk HEA | 4815.5
28.11_Stalen balk HEA | 4273

# IfcBeam: HEA320 (16)
In: 01 eerste verdieping
Type - Description: HEA320; PredefinedType: BEAM
Type - Pset_BeamCommon - LoadBearing: yes
Type - Pset_ConcreteElementGeneral - StructuralClass: S235; EnvironmentalClass: -
Type - Pset_FireRatingProperties - FireResistanceRating: 90
Type - Pset_ReinforcementBarPitchOfBeam - Description: HEA320
Classification: 28.11 hoofddraagconstructies; kolommen en liggers, kolom-/liggerconstructies (NL-Sfb)
Pset_BeamCommon - Slope: 0 deg; IsExternal: no; Reference: HEA320
Pset_QuantityTakeOff - Reference: HEA320; sets with these values: 2
ILS Ontwerp en Engineering - 4.3 Dragend: yes; 3.3 Bouwlaag: 01 eerste verdieping; 3.5 Naamgeving element: 28.11_Stalen balk HEA; 3.5 Type: HEA320; 3.6 NL-SfB omschrijving: hoofddraagconstructies; kolommen en liggers, kolom-/liggerconstructies; 4.5 C Brandwerendheid hoofddraagconstructie: 90; 4.8 Bouwfase: Nieuw; 4.8 C Sterkteklasse: S235; 4.8 C Milieuklasse: -
Name | Material = 4.7 Materiaal | Span (mm)
28.11_Stalen balk HEA | metaal_staal_profiel_s235 | 6507.5
28.11_Stalen balk HEA | metaal_staal_profiel_s235 | 6826.1
28.11_Stalen balk HEA | metaal_staal_profiel_s235 | 7785.4
28.11_Stalen balk HEA | metaal_staal_profiel_s235 | 6961.3
28.11_Stalen balk HEA | metaal_staal_profiel_s235 | 6963
28.11_Stalen balk HEA | metaal_staal_profiel_s235 | 3700.1
28.11_Stalen balk HEA | metaal_staal_profiel_s235 | 7848.4
28.11_Stalen balk HEA | metaal_staal_profiel_s235 | 4668.9
28.11_Stalen balk HEA | metaal_staal_profiel_s235 | 1456.1
28.11_Stalen balk HEA | metaal_staal_profiel_s235 | 2862
28.11_Stalen balk HEA | metaal_staal_profiel_s235 | 8216.7
28.11_Stalen balk HEA | metaal_staal_profiel_s235 | 13479.2
28.11_Stalen balk HEA | metaal_staal_profiel_s235 | 5378.8
28.11_Stalen balk HEA | metaal_staal_profiel_s235 | 6250.2
28.11_Stalen balk HEA | metaal_staal_profiel_s235 | 7492.5
28.11_Stalen balk HEA | metaal_staal_generiek | 4709.9

# IfcBeam: HEA400 (2)
In: 01 eerste verdieping
Type - Description: HEA400; PredefinedType: BEAM
Type - Pset_BeamCommon - LoadBearing: yes
Type - Pset_ConcreteElementGeneral - StructuralClass: S235; EnvironmentalClass: -
Type - Pset_FireRatingProperties - FireResistanceRating: 90
Type - Pset_ReinforcementBarPitchOfBeam - Description: HEA400
Classification: 28.11 hoofddraagconstructies; kolommen en liggers, kolom-/liggerconstructies (NL-Sfb); Material: metaal_staal_generiek
Pset_BeamCommon - Slope: 0 deg; IsExternal: no
Pset_QuantityTakeOff - sets with these values: 2
ILS Ontwerp en Engineering - 4.3 Dragend: yes; 3.3 Bouwlaag: 01 eerste verdieping; 3.5 Naamgeving element: 28.11_Stalen balk HEA; 3.5 Type: HEA400; 3.6 NL-SfB omschrijving: hoofddraagconstructies; kolommen en liggers, kolom-/liggerconstructies; 4.5 C Brandwerendheid hoofddraagconstructie: 90; 4.7 Materiaal: metaal_staal_generiek; 4.8 C Sterkteklasse: S235; 4.8 C Milieuklasse: -
Name | Pset_BeamCommon, Reference = Pset_QuantityTakeOff, Reference | Span (mm) | 4.8 Bouwfase
28.11_Stalen balk HEA | DIE40 | 14365 | Bestaand
28.11_Stalen balk HEA | HEA400 | 7005 | Nieuw

# IfcBeam: HEA550, 28.11_Stalen balk HEA
In: 01 eerste verdieping
Type - Description: HEA550; PredefinedType: BEAM
Type - Pset_BeamCommon - LoadBearing: yes
Type - Pset_ConcreteElementGeneral - StructuralClass: S235; EnvironmentalClass: -
Type - Pset_FireRatingProperties - FireResistanceRating: 90
Type - Pset_ReinforcementBarPitchOfBeam - Description: HEA550
Classification: 28.11 hoofddraagconstructies; kolommen en liggers, kolom-/liggerconstructies (NL-Sfb); Material: metaal_staal_generiek
Pset_BeamCommon - Slope: 0 deg; IsExternal: no; Reference: DIE55; Span: 7293.5 mm
Pset_QuantityTakeOff - Reference: DIE55; sets with these values: 2
ILS Ontwerp en Engineering - 4.3 Dragend: yes; 3.3 Bouwlaag: 01 eerste verdieping; 3.5 Naamgeving element: 28.11_Stalen balk HEA; 3.5 Type: HEA550; 3.6 NL-SfB omschrijving: hoofddraagconstructies; kolommen en liggers, kolom-/liggerconstructies; 4.5 C Brandwerendheid hoofddraagconstructie: 90; 4.7 Materiaal: metaal_staal_generiek; 4.8 Bouwfase: Bestaand; 4.8 C Sterkteklasse: S235; 4.8 C Milieuklasse: -

# IfcBeam: HEB120 (5)
In: 00 begane grond
Type - Description: HEB120; PredefinedType: BEAM
Type - Pset_BeamCommon - LoadBearing: yes
Type - Pset_ConcreteElementGeneral - StructuralClass: S235; EnvironmentalClass: -
Type - Pset_FireRatingProperties - FireResistanceRating: 90
Type - Pset_ReinforcementBarPitchOfBeam - Description: HEB120
Classification: 28.11 hoofddraagconstructies; kolommen en liggers, kolom-/liggerconstructies (NL-Sfb); Material: metaal_staal_generiek
Pset_BeamCommon - Slope: 0 deg; IsExternal: no; Reference: HEB120
Pset_QuantityTakeOff - Reference: HEB120; sets with these values: 2
ILS Ontwerp en Engineering - 4.3 Dragend: yes; 3.3 Bouwlaag: 00 begane grond; 3.5 Naamgeving element: 28.11_Stalen balk HEB; 3.5 Type: HEB120; 3.6 NL-SfB omschrijving: hoofddraagconstructies; kolommen en liggers, kolom-/liggerconstructies; 4.5 C Brandwerendheid hoofddraagconstructie: 90; 4.7 Materiaal: metaal_staal_generiek; 4.8 Bouwfase: Nieuw; 4.8 C Sterkteklasse: S235; 4.8 C Milieuklasse: -
Name | Span (mm)
28.11_Stalen balk HEB | 1275
2 x 28.11_Stalen balk HEB | 2857.5
2 x 28.11_Stalen balk HEB | 3170

# IfcBeam: HEB320 (9)
In: 01 eerste verdieping
Type - Description: HEB320; PredefinedType: BEAM
Type - Pset_BeamCommon - LoadBearing: yes
Type - Pset_ConcreteElementGeneral - StructuralClass: S235; EnvironmentalClass: -
Type - Pset_FireRatingProperties - FireResistanceRating: 90
Type - Pset_ReinforcementBarPitchOfBeam - Description: HEB320
Classification: 28.11 hoofddraagconstructies; kolommen en liggers, kolom-/liggerconstructies (NL-Sfb); Material: metaal_staal_profiel_s235
Pset_BeamCommon - Slope: 0 deg; IsExternal: no; Reference: HEB320
Pset_QuantityTakeOff - Reference: HEB320; sets with these values: 2
ILS Ontwerp en Engineering - 4.3 Dragend: yes; 3.3 Bouwlaag: 01 eerste verdieping; 3.5 Naamgeving element: 28.11_Stalen balk HEB; 3.5 Type: HEB320; 3.6 NL-SfB omschrijving: hoofddraagconstructies; kolommen en liggers, kolom-/liggerconstructies; 4.5 C Brandwerendheid hoofddraagconstructie: 90; 4.7 Materiaal: metaal_staal_profiel_s235; 4.8 Bouwfase: Nieuw; 4.8 C Sterkteklasse: S235; 4.8 C Milieuklasse: -
Name | Span (mm)
28.11_Stalen balk HEB | 20015.2
28.11_Stalen balk HEB | 19460.9
28.11_Stalen balk HEB | 19635.4
28.11_Stalen balk HEB | 18024.6
28.11_Stalen balk HEB | 17020.1
28.11_Stalen balk HEB | 15864.3
28.11_Stalen balk HEB | 19282.3
28.11_Stalen balk HEB | 4390.1
28.11_Stalen balk HEB | 25561.4

# IfcBeam: HEB400 (5)
In: 01 eerste verdieping
Type - Description: HEB400; PredefinedType: BEAM
Type - Pset_BeamCommon - LoadBearing: yes
Type - Pset_ConcreteElementGeneral - StructuralClass: S235; EnvironmentalClass: -
Type - Pset_FireRatingProperties - FireResistanceRating: 90
Type - Pset_ReinforcementBarPitchOfBeam - Description: HEB400
Classification: 28.11 hoofddraagconstructies; kolommen en liggers, kolom-/liggerconstructies (NL-Sfb); Material: metaal_staal_profiel_s235
Pset_BeamCommon - Slope: 0 deg; IsExternal: no; Reference: HEB400
Pset_QuantityTakeOff - Reference: HEB400; sets with these values: 2
ILS Ontwerp en Engineering - 4.3 Dragend: yes; 3.3 Bouwlaag: 01 eerste verdieping; 3.5 Naamgeving element: 28.11_Stalen balk HEB; 3.5 Type: HEB400; 3.6 NL-SfB omschrijving: hoofddraagconstructies; kolommen en liggers, kolom-/liggerconstructies; 4.5 C Brandwerendheid hoofddraagconstructie: 90; 4.7 Materiaal: metaal_staal_profiel_s235; 4.8 Bouwfase: Nieuw; 4.8 C Sterkteklasse: S235; 4.8 C Milieuklasse: -
Name | Span (mm)
28.11_Stalen balk HEB | 6975.2
28.11_Stalen balk HEB | 7124.3
28.11_Stalen balk HEB | 7273.4
28.11_Stalen balk HEB | 7422.5
28.11_Stalen balk HEB | 7571.6

# IfcBeam: K80x4, 28.11_SF_BalkKokerGelijkzijdig:K80x4:881914
In: 01 eerste verdieping
Type - PredefinedType: JOIST
Type - Pset_BeamCommon - LoadBearing: yes
Type - Pset_ReinforcementBarPitchOfBeam - Description: K80x4
Classification: 28.11 hoofddraagconstructies; kolommen en liggers, kolom-/liggerconstructies (NL-Sfb); Material: metaal_staal_generiek
Pset_BeamCommon - Slope: 0 deg; IsExternal: no; Reference: K80x4; Span: 4956.1 mm
Pset_QuantityTakeOff - Reference: K80x4; sets with these values: 2
ILS Ontwerp en Engineering - 4.3 Dragend: yes; 3.3 Bouwlaag: 01 eerste verdieping; 4.7 Materiaal: metaal_staal_generiek; 4.8 Bouwfase: Nieuw

# IfcBeam: K80x4, 28.11_SF_BalkKokerGelijkzijdig:K80x4:904954
In: 01 eerste verdieping
Type - Pset_BeamCommon - LoadBearing: yes
Type - Pset_ReinforcementBarPitchOfBeam - Description: K80x4
Classification: 28.11 hoofddraagconstructies; kolommen en liggers, kolom-/liggerconstructies (NL-Sfb); Material: metaal_staal_generiek
Pset_BeamCommon - Slope: 0 deg; IsExternal: no; Reference: K80x4; Span: 1479.2 mm
Pset_QuantityTakeOff - Reference: K80x4; sets with these values: 2
ILS Ontwerp en Engineering - 4.3 Dragend: yes; 3.3 Bouwlaag: 01 eerste verdieping; 4.7 Materiaal: metaal_staal_generiek; 4.8 Bouwfase: Nieuw

# IfcBeam: L150x15 (4)
In: 00 begane grond
Type - PredefinedType: BEAM
Type - Pset_BeamCommon - LoadBearing: yes
Type - Pset_ReinforcementBarPitchOfBeam - Description: L150x15
Description: {$type("IfcDescription[Type]")}; Classification: 28.11 hoofddraagconstructies; kolommen en liggers, kolom-/liggerconstructies (NL-Sfb); Material: metaal_staal_generiek
Pset_BeamCommon - Slope: 0 deg; IsExternal: no; Reference: L150x15
Pset_ConcreteElementGeneral - StructuralClass: {$type("StructuralClass[Type]")}; EnvironmentalClass: {$type("EnvironmentalClass[Type]")}
Pset_QuantityTakeOff - Reference: L150x15; sets with these values: 2
ILS Ontwerp en Engineering - 4.3 Dragend: yes; 3.3 Bouwlaag: 00 begane grond; 3.5 Type: {$type("IfcDescription[Type]")}; 3.6 NL-SfB omschrijving: hoofddraagconstructies; kolommen en liggers, kolom-/liggerconstructies; 4.7 Materiaal: metaal_staal_generiek; 4.8 Bouwfase: Nieuw; 4.8 C Sterkteklasse: {$type("StructuralClass[Type]")}; 4.8 C Milieuklasse: {$type("EnvironmentalClass[Type]")}
Name (28.11_SF_BalkL-Gelijkzijdig:L150x15:...) | Span (mm)
874398 | 3560
874425 | 3560
874971 | 3040
875126 | 3040

# IfcBeam: L70x7 (30)
In: 01 eerste verdieping
Type - PredefinedType: BEAM
Type - Pset_BeamCommon - LoadBearing: yes
Type - Pset_ReinforcementBarPitchOfBeam - Description: L70x7
Classification: 28.11 hoofddraagconstructies; kolommen en liggers, kolom-/liggerconstructies (NL-Sfb); Material: metaal_staal_generiek
Pset_BeamCommon - Slope: 0 deg; IsExternal: no; Reference: L70x7
Pset_QuantityTakeOff - Reference: L70x7; sets with these values: 2
ILS Ontwerp en Engineering - 4.3 Dragend: yes; 3.3 Bouwlaag: 01 eerste verdieping; 4.7 Materiaal: metaal_staal_generiek; 4.8 Bouwfase: Bestaand
Name (28.11_SF_WVB-L-Gelijkzijdig:L70x7:...) | Span (mm)
696034 | 8209.5
696096 | 8210
696671 | 5182.1
696949 | 8349.1
697020 | 8349.1
697294 | 8349.1
697351 | 8349.1
697571 | 8349.1
697629 | 8349
697852 | 8349.1
697973 | 8349.1
698091 | 8349.1
698238 | 8349
698421 | 7596.8
698457 | 8349.1
698601 | 7315
698710 | 8377.7
698854 | 8349.1
698987 | 8349
699083 | 5726.3
699143 | 6493.7
699752 | 8349.1
699799 | 8689.4
699894 | 8349.1
699956 | 8349.1
700014 | 8847
700116 | 8349
707015 | 6779.3
707077 | 4978.5
880703 | 4918.3

# IfcBeam: L70x7 (9)
In: 01 eerste verdieping
Type - PredefinedType: JOIST
Type - Pset_BeamCommon - LoadBearing: yes
Type - Pset_ReinforcementBarPitchOfBeam - Description: L70x7
Classification: 28.11 hoofddraagconstructies; kolommen en liggers, kolom-/liggerconstructies (NL-Sfb); Material: metaal_staal_generiek
Pset_BeamCommon - Slope: 0 deg; IsExternal: no; Reference: L70x7
Pset_QuantityTakeOff - Reference: L70x7; sets with these values: 2
ILS Ontwerp en Engineering - 4.3 Dragend: yes; 3.3 Bouwlaag: 01 eerste verdieping; 4.7 Materiaal: metaal_staal_generiek
Name (28.11_SF_WVB-L-Gelijkzijdig:L70x7:...) | Span (mm) | 4.8 Bouwfase
696484 | 7178.7 | Nieuw
698668 | 7315 | Bestaand
855881 | 2709.7 | Nieuw
879263 | 2612.2 | Nieuw
879514 | 3966 | Nieuw
879646 | 4884.7 | Nieuw
879784 | 4884.8 | Nieuw
882215 | 8349.1 | Nieuw
882624 | 7943.9 | Nieuw

# IfcBeam: L70x7 (30)
In: 01 eerste verdieping
Type - Pset_BeamCommon - LoadBearing: yes
Type - Pset_ReinforcementBarPitchOfBeam - Description: L70x7
Classification: 28.11 hoofddraagconstructies; kolommen en liggers, kolom-/liggerconstructies (NL-Sfb); Material: metaal_staal_generiek
Pset_BeamCommon - Slope: 0 deg; IsExternal: no; Reference: L70x7
Pset_QuantityTakeOff - Reference: L70x7; sets with these values: 2
ILS Ontwerp en Engineering - 4.3 Dragend: yes; 3.3 Bouwlaag: 01 eerste verdieping; 4.7 Materiaal: metaal_staal_generiek
Name | Span (mm) | 4.8 Bouwfase
28.11_Stalen balk HEA | 7852.4 | Bestaand | Description: {$type("IfcDescription[Type]")}; Pset_ConcreteElementGeneral - StructuralClass: {$type("StructuralClass[Type]")}; EnvironmentalClass: {$type("EnvironmentalClass[Type]")}; ILS Ontwerp en Engineering - 3.5 Naamgeving element: 28.11_Stalen balk HEA; 3.5 Type: {$type("IfcDescription[Type]")}; 3.6 NL-SfB omschrijving: hoofddraagconstructies; kolommen en liggers, kolom-/liggerconstructies; 4.8 C Sterkteklasse: {$type("StructuralClass[Type]")}; 4.8 C Milieuklasse: {$type("EnvironmentalClass[Type]")}
28.11_Stalen balk HEA | 7464.2 | Bestaand | Description: {$type("IfcDescription[Type]")}; Pset_ConcreteElementGeneral - StructuralClass: {$type("StructuralClass[Type]")}; EnvironmentalClass: {$type("EnvironmentalClass[Type]")}; ILS Ontwerp en Engineering - 3.5 Naamgeving element: 28.11_Stalen balk HEA; 3.5 Type: {$type("IfcDescription[Type]")}; 3.6 NL-SfB omschrijving: hoofddraagconstructies; kolommen en liggers, kolom-/liggerconstructies; 4.8 C Sterkteklasse: {$type("StructuralClass[Type]")}; 4.8 C Milieuklasse: {$type("EnvironmentalClass[Type]")}
28.11_SF_WVB-L-Gelijkzijdig:L70x7:696570 | 7178.6 | Nieuw
28.11_SF_WVB-L-Gelijkzijdig:L70x7:696738 | 5038.8 | Bestaand
28.11_SF_WVB-L-Gelijkzijdig:L70x7:696798 | 4306.3 | Bestaand
28.11_SF_WVB-L-Gelijkzijdig:L70x7:696852 | 4306.4 | Bestaand
28.11_SF_WVB-L-Gelijkzijdig:L70x7:697077 | 7616.7 | Bestaand
28.11_SF_WVB-L-Gelijkzijdig:L70x7:697122 | 6931.2 | Bestaand
28.11_SF_WVB-L-Gelijkzijdig:L70x7:697425 | 8349 | Bestaand
28.11_SF_WVB-L-Gelijkzijdig:L70x7:697506 | 8349.1 | Bestaand
28.11_SF_WVB-L-Gelijkzijdig:L70x7:697767 | 8349.1 | Bestaand
28.11_SF_WVB-L-Gelijkzijdig:L70x7:697924 | 8349.1 | Bestaand
28.11_SF_WVB-L-Gelijkzijdig:L70x7:698035 | 8349.1 | Bestaand
28.11_SF_WVB-L-Gelijkzijdig:L70x7:698160 | 8349.1 | Bestaand
28.11_SF_WVB-L-Gelijkzijdig:L70x7:698296 | 8349.1 | Bestaand
28.11_SF_WVB-L-Gelijkzijdig:L70x7:698369 | 8377.8 | Bestaand
28.11_SF_WVB-L-Gelijkzijdig:L70x7:698540 | 8532.9 | Bestaand
28.11_SF_WVB-L-Gelijkzijdig:L70x7:698778 | 8532.9 | Bestaand
28.11_SF_WVB-L-Gelijkzijdig:L70x7:698932 | 8689.3 | Bestaand
28.11_SF_WVB-L-Gelijkzijdig:L70x7:699849 | 8847 | Bestaand
28.11_SF_WVB-L-Gelijkzijdig:L70x7:700071 | 9150.3 | Bestaand
28.11_SF_WVB-L-Gelijkzijdig:L70x7:856000 | 2709.7 | Nieuw
28.11_SF_WVB-L-Gelijkzijdig:L70x7:879264 | 1733.4 | Nieuw
28.11_SF_WVB-L-Gelijkzijdig:L70x7:879924 | 3280.9 | Nieuw
28.11_SF_WVB-L-Gelijkzijdig:L70x7:880018 | 3288.6 | Nieuw
28.11_SF_WVB-L-Gelijkzijdig:L70x7:880298 | 4795.5 | Nieuw
28.11_SF_WVB-L-Gelijkzijdig:L70x7:880419 | 4797.5 | Nieuw
28.11_SF_WVB-L-Gelijkzijdig:L70x7:880546 | 5166.3 | Bestaand
28.11_SF_WVB-L-Gelijkzijdig:L70x7:882443 | 7178.6 | Nieuw
28.11_SF_WVB-L-Gelijkzijdig:L70x7:882506 | 8208.6 | Nieuw

# IfcBeam: STRIP 10x100 (2)
In: 00 begane grond
Type - PredefinedType: BEAM
Type - Pset_BeamCommon - LoadBearing: yes
Type - Pset_ReinforcementBarPitchOfBeam - Description: wvb STRIP 10x100
Material: metaal_staal_generiek
Pset_BeamCommon - IsExternal: no; Reference: STRIP 10x100
Pset_QuantityTakeOff - Reference: STRIP 10x100; sets with these values: 2
ILS Ontwerp en Engineering - 4.3 Dragend: yes; 3.3 Bouwlaag: 00 begane grond; 4.7 Materiaal: metaal_staal_generiek; 4.8 Bouwfase: Nieuw
Name (28.11_SF_WVB-Strip:STRIP 10x100:...) | Span (mm) | Slope (deg)
907325 | 5786.7 | 66.5804
907370 | 5152 | 63.4847

# IfcBeam: STRIP 10x100 (12)
Type - Pset_BeamCommon - LoadBearing: yes
Type - Pset_ReinforcementBarPitchOfBeam - Description: wvb STRIP 10x100
Material: metaal_staal_generiek
Pset_BeamCommon - IsExternal: no; Reference: STRIP 10x100
Pset_QuantityTakeOff - Reference: STRIP 10x100; sets with these values: 2
ILS Ontwerp en Engineering - 4.3 Dragend: yes; 4.7 Materiaal: metaal_staal_generiek; 4.8 Bouwfase: Nieuw
Name (28.11_SF_WVB-Strip:STRIP 10x100:...) | In | Span (mm) | Slope (deg) | 3.3 Bouwlaag
905094 | 00 begane grond | 5936.2 | 48.5589 | 00 begane grond
905180 | 00 begane grond | 5928.8 | 48.495 | 00 begane grond
905317 | 01 eerste verdieping | 4040.5 | 68.5247 | 01 eerste verdieping
905436 | 01 eerste verdieping | 4040.5 | 68.5247 | 01 eerste verdieping
906190 | 00 begane grond | 3592.7 | 45.6721 | 00 begane grond
906294 | 00 begane grond | 3459.3 | 43.4726 | 00 begane grond
906369 | 01 eerste verdieping | 3136.3 | 36.8289 | 01 eerste verdieping
906451 | 00 begane grond | 3136.4 | 36.829 | 00 begane grond
906510 | 01 eerste verdieping | 5167.1 | 21.3363 | 01 eerste verdieping
906578 | 00 begane grond | 5167.8 | 21.3332 | 00 begane grond
907604 | 00 begane grond | 7039.2 | 39.2109 | 00 begane grond
907665 | 00 begane grond | 7039.2 | 39.2109 | 00 begane grond

# IfcBeam: STRIP 8x80 (6)
In: 00 begane grond
Type - Pset_BeamCommon - LoadBearing: yes
Type - Pset_ReinforcementBarPitchOfBeam - Description: w.v.b. STRIP 8x80
Material: metaal_staal_generiek
Pset_BeamCommon - IsExternal: no; Reference: STRIP 8x80
Pset_QuantityTakeOff - Reference: STRIP 8x80; sets with these values: 2
ILS Ontwerp en Engineering - 4.3 Dragend: yes; 3.3 Bouwlaag: 00 begane grond; 4.7 Materiaal: metaal_staal_generiek; 4.8 Bouwfase: Nieuw
Name (28.11_SF_WVB-Strip:STRIP 8x80:...) | Span (mm) | Slope (deg)
843424 | 6089 | 38.976
843479 | 6089 | 38.976
854235 | 6089.1 | 38.976
854279 | 6089 | 38.976
854321 | 6057.8 | 38.6084
854365 | 6089 | 38.976

# IfcBeam: UNP200 (2)
In: 00 begane grond
Type - PredefinedType: BEAM
Type - Pset_BeamCommon - LoadBearing: yes
Type - Pset_ReinforcementBarPitchOfBeam - Description: UNP200
Classification: 28.11 hoofddraagconstructies; kolommen en liggers, kolom-/liggerconstructies (NL-Sfb); Material: metaal_staal_generiek
Pset_BeamCommon - Slope: 0 deg; IsExternal: no; Span: 4730 mm; Reference: UNP200
Pset_QuantityTakeOff - Reference: UNP200; sets with these values: 2
ILS Ontwerp en Engineering - 4.3 Dragend: yes; 3.3 Bouwlaag: 00 begane grond; 4.7 Materiaal: metaal_staal_generiek; 4.8 Bouwfase: Nieuw
Name (28.11_SF_BalkUNP:UNP200:...)
797711
797865

# IfcBeam: UNP240 (6)
In: 01 eerste verdieping
Type - Pset_BeamCommon - LoadBearing: yes
Type - Pset_ReinforcementBarPitchOfBeam - Description: UNP240
Classification: 28.11 hoofddraagconstructies; kolommen en liggers, kolom-/liggerconstructies (NL-Sfb); Material: metaal_staal_generiek
Pset_BeamCommon - IsExternal: no; Reference: UNP240
Pset_QuantityTakeOff - Reference: UNP240; sets with these values: 2
ILS Ontwerp en Engineering - 4.3 Dragend: yes; 3.3 Bouwlaag: 01 eerste verdieping; 4.7 Materiaal: metaal_staal_generiek
Name (28.11_SF_BalkUNP:UNP240:...) | Slope (deg) | Span (mm) | 4.8 Bouwfase
701902 | 0 | 5759.5 | Bestaand
842011 | 0.000338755 | 4400 | Nieuw
842498 | 0.000338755 | 4400 | Nieuw
892716 | 0 | 6505.7 | Nieuw
892770 | 0 | 6620 | Nieuw
892938 | 0 | 6647.1 | Nieuw

# IfcBeam: balk 350x600mm (6)
In: 00 begane grond
Type - Description: balk 350x600mm; PredefinedType: BEAM
Type - Pset_BeamCommon - LoadBearing: yes
Type - Pset_ConcreteElementGeneral - StructuralClass: -; EnvironmentalClass: -
Type - Pset_FireRatingProperties - FireResistanceRating: -
Type - Pset_ReinforcementBarPitchOfBeam - Description: balk 350x600mm
Classification: 16.12 funderingsconstructies; voeten en balken, fundatie balken (NL-Sfb); Material: beton_gewapend_ihw
Pset_BeamCommon - Slope: 0 deg; IsExternal: no; Reference: balk 350x600mm
Pset_QuantityTakeOff - Reference: balk 350x600mm; sets with these values: 2
ILS Ontwerp en Engineering - 4.3 Dragend: yes; 3.3 Bouwlaag: 00 begane grond; 3.5 Naamgeving element: 16.12_Beton balk; 3.5 Type: balk 350x600mm; 3.6 NL-SfB omschrijving: funderingsconstructies; voeten en balken, fundatie balken; 4.5 C Brandwerendheid hoofddraagconstructie: -; 4.7 Materiaal: beton_gewapend_ihw; 4.8 Bouwfase: Bestaand; 4.8 C Wapeningshoeveelheid: 75,00 kg/m³
Name | Span (mm)
16.12_Beton balk | 4719.17
2 x 16.12_Beton balk | 5880
16.12_Beton balk | 7073.15
16.12_Beton balk | 5622.71
16.12_Beton balk | 6729.82

# IfcBeam: balk 350x600mm (8)
In: 00 begane grond
Type - PredefinedType: BEAM; Classification: 28.11 hoofddraagconstructies; kolommen en liggers, kolom-/liggerconstructies (NL-Sfb); Material: beton_gewapend_ihw
Type - Pset_BeamCommon - LoadBearing: yes
Type - Pset_ConcreteElementGeneral - StructuralClass: -; EnvironmentalClass: -
Type - Pset_ReinforcementBarPitchOfBeam - Description: balk 350x600mm
Pset_BeamCommon - Slope: 0 deg; IsExternal: no; Reference: balk 350x600mm
Pset_QuantityTakeOff - Reference: balk 350x600mm; sets with these values: 2
ILS Ontwerp en Engineering - 4.3 Dragend: yes; 3.3 Bouwlaag: 00 begane grond; 4.7 Materiaal: beton_gewapend_ihw; 4.8 Bouwfase: Bestaand
Name (28.11_SF_BetonBalk:balk 350x600mm:...) | Span (mm)
621848 | 15970.9
621898 | 17233.5
621933 | 15934.7
622005 | 12664.2
622046 | 18132
622088 | 17010
622121 | 16468.6
622164 | 15403.4

# IfcBuildingElementProxy: 850x370, 33.22_GM_SparingZone:850x370:835035
In: 00 begane grond
Type - PredefinedType: USERDEFINED; Classification: 33.22 vloeropeningen; gevuld, niet-beloopbare vullingen (NL-Sfb); Material: ntb_ntb_generiek_sparingzone
Pset_BuildingElementProxyCommon - Reference: 850x370; sets with these values: 2
ILS Ontwerp en Engineering - 3.3 Bouwlaag: 00 begane grond; 4.8 Bouwfase: Nieuw
Pset_ProvisionForVoid - Width: 370 mm; Height: 850 mm; Depth: 850 mm

# IfcBuildingElementProxy: 900x370mm, 33.22_GM_SparingZone:900x370mm:835172
In: 00 begane grond
Type - PredefinedType: USERDEFINED; Classification: 33.22 vloeropeningen; gevuld, niet-beloopbare vullingen (NL-Sfb); Material: ntb_ntb_generiek_sparingzone
Pset_BuildingElementProxyCommon - Reference: 900x370mm; sets with these values: 2
ILS Ontwerp en Engineering - 3.3 Bouwlaag: 00 begane grond; 4.8 Bouwfase: Nieuw
Pset_ProvisionForVoid - Width: 370 mm; Height: 900 mm; Depth: 900 mm

# IfcBuildingElementProxy: EPA, 01_GM_ReferentieKubus:EPA:21476
In: 00 begane grond
Type - Material: 00_EPA_Paars, 00_EPA_Rood, 00_EPA_Groen, 00_EPA_Wit
Pset_BuildingElementProxyCommon - Reference: EPA; sets with these values: 2
ILS Ontwerp en Engineering - 3.3 Bouwlaag: 00 begane grond; 4.8 Bouwfase: Nieuw

# IfcColumn: 450x1250mm, 28.11_SCO_BetonKolomRechthoek:450x1250mm:617643
In: -1 kelder
Type - PredefinedType: COLUMN; Classification: 28.11 hoofddraagconstructies; kolommen en liggers, kolom-/liggerconstructies (NL-Sfb); Material: beton_gewapend_ihw
Type - Pset_ColumnCommon - LoadBearing: yes
Type - Pset_ReinforcementBarPitchOfColumn - Description: 450x1250mm
Pset_ColumnCommon - Slope: 0 deg; IsExternal: no; Reference: 450x1250mm
Pset_QuantityTakeOff - Reference: 450x1250mm; sets with these values: 2
ILS Ontwerp en Engineering - 3.3 Bouwlaag: -1 kelder; 4.7 Materiaal: beton_gewapend_ihw; 4.8 Bouwfase: Bestaand

# IfcColumn: 450x450mm (26)
In: -1 kelder
Type - PredefinedType: COLUMN; Classification: 28.11 hoofddraagconstructies; kolommen en liggers, kolom-/liggerconstructies (NL-Sfb); Material: beton_gewapend_ihw
Type - Pset_ColumnCommon - LoadBearing: yes
Type - Pset_ReinforcementBarPitchOfColumn - Description: 450x450mm
Pset_ColumnCommon - Reference: 450x450mm; IsExternal: no
Pset_QuantityTakeOff - Reference: 450x450mm; sets with these values: 2
ILS Ontwerp en Engineering - 3.3 Bouwlaag: -1 kelder; 4.7 Materiaal: beton_gewapend_ihw; 4.8 Bouwfase: Bestaand
Name (28.11_SCO_BetonKolomRechthoek:450x450mm:...) | Slope (deg)
617384 | 0
617838 | 0
617850 | 0
617862 | 0
617872
617882
617892 | 0
617902 | 0
617914 | 0
617932
617944
617952
617962
617972 | 0
617988 | 0
617996 | 0
618006 | 0
618018
618030 | 0
618042 | 0
618052
618064 | 0
618130
618189 | 0
618190
622492

# IfcColumn: 450x650mm, 28.11_SCO_BetonKolomRechthoek:450x650mm:617609
In: -1 kelder
Type - PredefinedType: COLUMN; Classification: 28.11 hoofddraagconstructies; kolommen en liggers, kolom-/liggerconstructies (NL-Sfb); Material: beton_gewapend_ihw
Type - Pset_ColumnCommon - LoadBearing: yes
Type - Pset_ReinforcementBarPitchOfColumn - Description: 450x650mm
Pset_ColumnCommon - Slope: 0 deg; IsExternal: no; Reference: 450x650mm
Pset_QuantityTakeOff - Reference: 450x650mm; sets with these values: 2
ILS Ontwerp en Engineering - 3.3 Bouwlaag: -1 kelder; 4.7 Materiaal: beton_gewapend_ihw; 4.8 Bouwfase: Bestaand

# IfcColumn: 450x850mm, 28.11_SCO_BetonKolomRechthoek:450x850mm:617619
In: -1 kelder
Type - PredefinedType: COLUMN; Classification: 28.11 hoofddraagconstructies; kolommen en liggers, kolom-/liggerconstructies (NL-Sfb); Material: beton_gewapend_ihw
Type - Pset_ColumnCommon - LoadBearing: yes
Type - Pset_ReinforcementBarPitchOfColumn - Description: 450x850mm
Pset_ColumnCommon - Slope: 0 deg; IsExternal: no; Reference: 450x850mm
Pset_QuantityTakeOff - Reference: 450x850mm; sets with these values: 2
ILS Ontwerp en Engineering - 3.3 Bouwlaag: -1 kelder; 4.7 Materiaal: beton_gewapend_ihw; 4.8 Bouwfase: Bestaand

# IfcColumn: 450x900mm, 28.11_SCO_BetonKolomRechthoek:450x900mm:617631
In: -1 kelder
Type - PredefinedType: COLUMN; Classification: 28.11 hoofddraagconstructies; kolommen en liggers, kolom-/liggerconstructies (NL-Sfb); Material: beton_gewapend_ihw
Type - Pset_ColumnCommon - LoadBearing: yes
Type - Pset_ReinforcementBarPitchOfColumn - Description: 450x900mm
Pset_ColumnCommon - IsExternal: no; Reference: 450x900mm
Pset_QuantityTakeOff - Reference: 450x900mm; sets with these values: 2
ILS Ontwerp en Engineering - 3.3 Bouwlaag: -1 kelder; 4.7 Materiaal: beton_gewapend_ihw; 4.8 Bouwfase: Bestaand

# IfcColumn: DIE16 (19)
In: 01 eerste verdieping
Type - PredefinedType: COLUMN; Classification: 28.11 hoofddraagconstructies; kolommen en liggers, kolom-/liggerconstructies (NL-Sfb); Material: metaal_staal_generiek
Type - Pset_ColumnCommon - LoadBearing: yes
Type - Pset_ReinforcementBarPitchOfColumn - Description: DIE16
Pset_ColumnCommon - IsExternal: no; Reference: DIE16
Pset_QuantityTakeOff - Reference: DIE16; sets with these values: 2
ILS Ontwerp en Engineering - 3.3 Bouwlaag: 01 eerste verdieping; 4.7 Materiaal: metaal_staal_generiek; 4.8 Bouwfase: Bestaand
Name (28.11_SCO_KolomHEA:DIE16:...)
710117
710365
711300
714862
715439
715666
715893
716096
716587
716952
717297
717484
720252
721020
721155
721382
721749
722130
722373

# IfcColumn: DIE18 (25)
Type - PredefinedType: COLUMN; Classification: 28.11 hoofddraagconstructies; kolommen en liggers, kolom-/liggerconstructies (NL-Sfb); Material: metaal_staal_generiek
Type - Pset_ColumnCommon - LoadBearing: yes
Type - Pset_ReinforcementBarPitchOfColumn - Description: DIE18
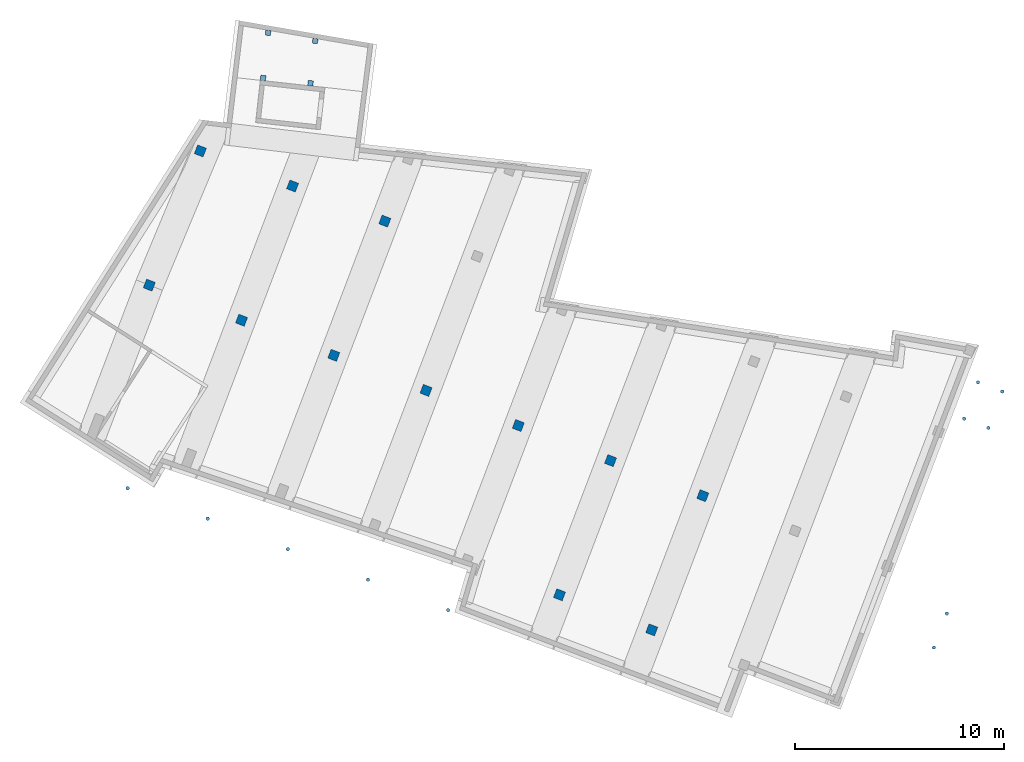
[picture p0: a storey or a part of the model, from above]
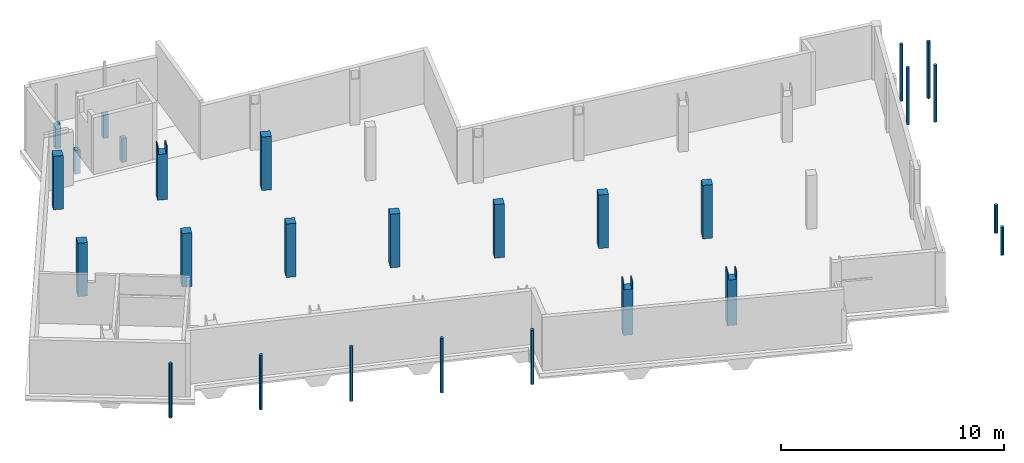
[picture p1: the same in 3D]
Properties of the parts of a building model (IFC2X3), part 2 of 2

# IfcColumn: DIE18 (25)
Pset_ColumnCommon - IsExternal: no; Reference: DIE18
Pset_QuantityTakeOff - Reference: DIE18; sets with these values: 2
ILS Ontwerp en Engineering - 4.7 Materiaal: metaal_staal_generiek
Name (28.11_SCO_KolomHEA:DIE18:...) | In | 3.3 Bouwlaag | 4.8 Bouwfase
654995 | 00 begane grond | 00 begane grond | Bestaand
656698 | 00 begane grond | 00 begane grond | Bestaand
656759 | 00 begane grond | 00 begane grond | Bestaand
657128 | 00 begane grond | 00 begane grond | Bestaand
657235 | 00 begane grond | 00 begane grond | Bestaand
657350 | 00 begane grond | 00 begane grond | Bestaand | Pset_ColumnCommon - Slope: 0 deg
658127 | 00 begane grond | 00 begane grond | Bestaand
658420 | 00 begane grond | 00 begane grond | Bestaand
658787 | 00 begane grond | 00 begane grond | Bestaand
658824 | 00 begane grond | 00 begane grond | Bestaand | Pset_ColumnCommon - Slope: 0 deg
658973 | 00 begane grond | 00 begane grond | Bestaand
659120 | 00 begane grond | 00 begane grond | Bestaand | Pset_ColumnCommon - Slope: 0 deg
659792 | 00 begane grond | 00 begane grond | Bestaand
660235 | 00 begane grond | 00 begane grond | Bestaand
660511 | 00 begane grond | 00 begane grond | Bestaand
660722 | 00 begane grond | 00 begane grond | Bestaand
661168 | 00 begane grond | 00 begane grond | Bestaand
674748 | 00 begane grond | 00 begane grond | Bestaand
675143 | 00 begane grond | 00 begane grond | Bestaand
720436 | 01 eerste verdieping | 01 eerste verdieping | Bestaand
720581 | 01 eerste verdieping | 01 eerste verdieping | Bestaand
720844 | 01 eerste verdieping | 01 eerste verdieping | Bestaand
723116 | 00 begane grond | 00 begane grond | Nieuw | Pset_ColumnCommon - Slope: 0 deg
723155 | 00 begane grond | 00 begane grond | Bestaand | Pset_ColumnCommon - Slope: 0 deg
723169 | 00 begane grond | 00 begane grond | Bestaand | Pset_ColumnCommon - Slope: 0 deg

# IfcColumn: DIE22 (26)
Type - PredefinedType: COLUMN; Classification: 28.11 hoofddraagconstructies; kolommen en liggers, kolom-/liggerconstructies (NL-Sfb); Material: metaal_staal_generiek
Type - Pset_ColumnCommon - LoadBearing: yes
Type - Pset_ReinforcementBarPitchOfColumn - Description: DIE22
Pset_ColumnCommon - IsExternal: no; Reference: DIE22
Pset_QuantityTakeOff - Reference: DIE22; sets with these values: 2
ILS Ontwerp en Engineering - 4.7 Materiaal: metaal_staal_generiek; 4.8 Bouwfase: Bestaand
Name (28.11_SCO_KolomHEA:DIE22:...) | In | 3.3 Bouwlaag
654552 | 00 begane grond | 00 begane grond
654728 | 00 begane grond | 00 begane grond
654821 | 00 begane grond | 00 begane grond
711936 | 01 eerste verdieping | 01 eerste verdieping
712218 | 01 eerste verdieping | 01 eerste verdieping
712605 | 01 eerste verdieping | 01 eerste verdieping
713132 | 01 eerste verdieping | 01 eerste verdieping
713411 | 01 eerste verdieping | 01 eerste verdieping
713690 | 01 eerste verdieping | 01 eerste verdieping
713941 | 01 eerste verdieping | 01 eerste verdieping
714180 | 01 eerste verdieping | 01 eerste verdieping
717910 | 01 eerste verdieping | 01 eerste verdieping
718321 | 01 eerste verdieping | 01 eerste verdieping
718446 | 01 eerste verdieping | 01 eerste verdieping
718631 | 01 eerste verdieping | 01 eerste verdieping
718857 | 01 eerste verdieping | 01 eerste verdieping
718964 | 01 eerste verdieping | 01 eerste verdieping
719147 | 01 eerste verdieping | 01 eerste verdieping
719234 | 01 eerste verdieping | 01 eerste verdieping
719431 | 01 eerste verdieping | 01 eerste verdieping
719500 | 01 eerste verdieping | 01 eerste verdieping
719681 | 01 eerste verdieping | 01 eerste verdieping
719788 | 01 eerste verdieping | 01 eerste verdieping
719901 | 01 eerste verdieping | 01 eerste verdieping
719974 | 01 eerste verdieping | 01 eerste verdieping
883876 | 01 eerste verdieping | 01 eerste verdieping

# IfcColumn: DIE26 (25)
In: 00 begane grond
Type - PredefinedType: COLUMN; Classification: 28.11 hoofddraagconstructies; kolommen en liggers, kolom-/liggerconstructies (NL-Sfb); Material: metaal_staal_generiek
Type - Pset_ColumnCommon - LoadBearing: yes
Type - Pset_ReinforcementBarPitchOfColumn - Description: DIE26
Pset_ColumnCommon - IsExternal: no; Reference: DIE26
Pset_QuantityTakeOff - Reference: DIE26; sets with these values: 2
ILS Ontwerp en Engineering - 3.3 Bouwlaag: 00 begane grond; 4.7 Materiaal: metaal_staal_generiek; 4.8 Bouwfase: Bestaand
Name (28.11_SCO_KolomHEA:DIE26:...)
652760
652903
652972
653151
653198
653449
653546
653683
653810
654055
654134
654209
654286
654382
655232
655441
655534
655629
656338
656447
656532
661242
661532
672648 | Pset_ColumnCommon - Slope: 0 deg
672938 | Pset_ColumnCommon - Slope: 0 deg

# IfcColumn: HEA200 (11)
Type - PredefinedType: COLUMN; Classification: 28.11 hoofddraagconstructies; kolommen en liggers, kolom-/liggerconstructies (NL-Sfb); Material: metaal_staal_generiek
Type - Pset_ColumnCommon - LoadBearing: yes
Type - Pset_ReinforcementBarPitchOfColumn - Description: HEA200
Pset_ColumnCommon - IsExternal: no; Reference: HEA200
Pset_QuantityTakeOff - Reference: HEA200; sets with these values: 2
ILS Ontwerp en Engineering - 4.7 Materiaal: metaal_staal_generiek; 4.8 Bouwfase: Nieuw
Name (28.11_SCO_KolomHEA:HEA200:...) | In | 3.3 Bouwlaag
871930 | 01 eerste verdieping | 01 eerste verdieping
872098 | 01 eerste verdieping | 01 eerste verdieping
872109 | 01 eerste verdieping | 01 eerste verdieping
872118 | 01 eerste verdieping | 01 eerste verdieping
872127 | 01 eerste verdieping | 01 eerste verdieping
904433 | 00 begane grond | 00 begane grond | Pset_ColumnCommon - Slope: 0 deg
904433 | 01 eerste verdieping | 00 begane grond | Pset_ColumnCommon - Slope: 0 deg
905529 | 00 begane grond | 00 begane grond
905989 | 01 eerste verdieping | 01 eerste verdieping
907469 | 00 begane grond | 00 begane grond
907469 | 01 eerste verdieping | 00 begane grond

# IfcColumn: K100x10 (10)
Type - Description: K100x10; PredefinedType: COLUMN; Classification: 28.11 hoofddraagconstructies; kolommen en liggers, kolom-/liggerconstructies (NL-Sfb); Material: metaal_staal_generiek
Type - Pset_ColumnCommon - LoadBearing: yes
Type - Pset_ConcreteElementGeneral - StructuralClass: S275; EnvironmentalClass: -
Type - Pset_FireRatingProperties - FireResistanceRating: 90
Type - Pset_ReinforcementBarPitchOfColumn - Description: K100x10
Pset_ColumnCommon - IsExternal: no; Reference: K100x10; FireRating: -
Pset_ConcreteElementGeneral - FireRating: -
Pset_QuantityTakeOff - Reference: K100x10; sets with these values: 2
ILS Ontwerp en Engineering - 4.3 Dragend: yes; 3.3 Bouwlaag: -1 kelder; 3.5 Naamgeving element: 28.11_Kolom koker gelijkzijdig; 3.5 Type: K100x10; 4.5 B Brandwerendheid (WBDBO): -; 4.5 C Brandwerendheid hoofddraagconstructie: 90; 4.7 Materiaal: metaal_staal_generiek; 4.8 Bouwfase: Nieuw; 4.8 C Sterkteklasse: S275; 4.8 C Milieuklasse: -
Name | In | Slope (deg)
4 x 28.11_Kolom koker gelijkzijdig | -1 kelder | 0
2 x 28.11_Kolom koker gelijkzijdig | -1 kelder
2 x 28.11_Kolom koker gelijkzijdig | 00 begane grond | 0
2 x 28.11_Kolom koker gelijkzijdig | 01 eerste verdieping | 0

# IfcColumn: UNP200 (2)
Type - PredefinedType: COLUMN; Classification: 28.11 hoofddraagconstructies; kolommen en liggers, kolom-/liggerconstructies (NL-Sfb); Material: metaal_staal_generiek
Type - Pset_ColumnCommon - LoadBearing: yes
Type - Pset_ReinforcementBarPitchOfColumn - Description: UNP200
Pset_ColumnCommon - Slope: 0 deg; IsExternal: no; Reference: UNP200
Pset_QuantityTakeOff - Reference: UNP200; sets with these values: 2
ILS Ontwerp en Engineering - 3.3 Bouwlaag: 00 begane grond; 4.7 Materiaal: metaal_staal_generiek; 4.8 Bouwfase: Nieuw
Name (28.11_SCO_KolomUNP:UNP200:...) | In
903651 | 00 begane grond
903651 | 01 eerste verdieping

# IfcColumn: UNP260 (4)
Type - PredefinedType: COLUMN; Classification: 28.11 hoofddraagconstructies; kolommen en liggers, kolom-/liggerconstructies (NL-Sfb); Material: metaal_staal_generiek
Type - Pset_ColumnCommon - LoadBearing: yes
Type - Pset_ReinforcementBarPitchOfColumn - Description: UNP260
Pset_ColumnCommon - IsExternal: no; Reference: UNP260
Pset_QuantityTakeOff - Reference: UNP260; sets with these values: 2
ILS Ontwerp en Engineering - 3.3 Bouwlaag: 00 begane grond; 4.7 Materiaal: metaal_staal_generiek; 4.8 Bouwfase: Nieuw
Name (28.11_SCO_KolomUNP:UNP260:...) | In
903104 | 00 begane grond | Pset_ColumnCommon - Slope: 0 deg
903104 | 01 eerste verdieping | Pset_ColumnCommon - Slope: 0 deg
905709 | 00 begane grond
905709 | 01 eerste verdieping

# IfcFooting: 500x500x500mm (4)
In: -1 kelder
Type - Description: opstort 250x250x1300mm; Classification: 16.13 funderingsconstructies; voeten en balken, fundatie poeren (NL-Sfb); Material: beton_gewapend_ihw_c30/37
PredefinedType: USERDEFINED
Pset_ConcreteElementGeneral - StructuralClass: C30/37; EnvironmentalClass: XC1; FireRating: -
Pset_FireRatingProperties - FireResistanceRating: 90
Pset_QuantityTakeOff - Reference: 250x250x1300mm
Pset_ReinforcementBarCountOfIndependentFooting - Description: opstort 250x250x1300mm; Reference: 250x250x1300mm; sets with these values: 2
ILS Ontwerp en Engineering - 4.3 Dragend: yes; 3.3 Bouwlaag: Level : -1 kelder; 3.5 Naamgeving element: 16.11_Opstort; 3.5 Type: opstort 250x250x1300mm; 3.6 NL-SfB code: 16.13; 3.6 NL-SfB omschrijving: funderingsconstructies; voeten en balken, fundatie poeren; 4.5 B Brandwerendheid (WBDBO): -; 4.5 C Brandwerendheid hoofddraagconstructie: 90; 4.7 Materiaal: beton_gewapend_ihw_c30/37; 4.8 Bouwfase: Nieuw; 4.8 C Sterkteklasse: C30/37; 4.8 C Milieuklasse: XC1; 4.8 C Wapeningshoeveelheid: 75,00 kg/m³

# IfcFooting: poer 1000x1000x800mm (4)
In: 00 begane grond
Type - Description: poer 1000x1000x800mm; Classification: 16.13 funderingsconstructies; voeten en balken, fundatie poeren (NL-Sfb); Material: beton_gewapend_ihw
PredefinedType: PILE_CAP
Pset_ConcreteElementGeneral - StructuralClass: -; EnvironmentalClass: -
Pset_FireRatingProperties - FireResistanceRating: -
Pset_QuantityTakeOff - Reference: 1000x1000x800mm
Pset_ReinforcementBarCountOfIndependentFooting - Description: poer 1000x1000x800mm; Reference: 1000x1000x800mm; sets with these values: 2
ILS Ontwerp en Engineering - 4.3 Dragend: yes; 3.3 Bouwlaag: Level : 00 begane grond; 3.5 Naamgeving element: 16.13_Poer rechthoek; 3.5 Type: poer 1000x1000x800mm; 3.6 NL-SfB code: 16.13; 3.6 NL-SfB omschrijving: funderingsconstructies; voeten en balken, fundatie poeren; 4.5 C Brandwerendheid hoofddraagconstructie: -; 4.7 Materiaal: beton_gewapend_ihw; 4.8 Bouwfase: Bestaand; 4.8 C Sterkteklasse: -; 4.8 C Milieuklasse: -; 4.8 C Wapeningshoeveelheid: 75,00 kg/m³

# IfcFooting: poer 500x1000x1170mm (4)
In: 00 begane grond
Type - Description: poer 500x1000x1170mm; Classification: 16.13 funderingsconstructies; voeten en balken, fundatie poeren (NL-Sfb); Material: beton_gewapend_ihw
PredefinedType: PILE_CAP
Pset_ConcreteElementGeneral - StructuralClass: -; EnvironmentalClass: -
Pset_FireRatingProperties - FireResistanceRating: -
Pset_QuantityTakeOff - Reference: 500x1000x1170mm
Pset_ReinforcementBarCountOfIndependentFooting - Description: poer 500x1000x1170mm; Reference: 500x1000x1170mm; sets with these values: 2
ILS Ontwerp en Engineering - 4.3 Dragend: yes; 3.3 Bouwlaag: Level : 00 begane grond; 3.5 Naamgeving element: 16.13_Poer rechthoek; 3.5 Type: poer 500x1000x1170mm; 3.6 NL-SfB code: 16.13; 3.6 NL-SfB omschrijving: funderingsconstructies; voeten en balken, fundatie poeren; 4.5 C Brandwerendheid hoofddraagconstructie: -; 4.7 Materiaal: beton_gewapend_ihw; 4.8 Bouwfase: Bestaand; 4.8 C Sterkteklasse: -; 4.8 C Milieuklasse: -; 4.8 C Wapeningshoeveelheid: 75,00 kg/m³

# IfcFooting: poer 500x1000x800mm (2)
In: 00 begane grond
Type - Description: poer 500x1000x800mm; Classification: 16.13 funderingsconstructies; voeten en balken, fundatie poeren (NL-Sfb); Material: beton_gewapend_ihw
PredefinedType: PILE_CAP
Pset_ConcreteElementGeneral - StructuralClass: -; EnvironmentalClass: -
Pset_FireRatingProperties - FireResistanceRating: -
Pset_QuantityTakeOff - Reference: 500x1000x800mm
Pset_ReinforcementBarCountOfIndependentFooting - Description: poer 500x1000x800mm; Reference: 500x1000x800mm; sets with these values: 2
ILS Ontwerp en Engineering - 4.3 Dragend: yes; 3.3 Bouwlaag: Level : 00 begane grond; 3.5 Naamgeving element: 16.13_Poer rechthoek; 3.5 Type: poer 500x1000x800mm; 3.6 NL-SfB code: 16.13; 3.6 NL-SfB omschrijving: funderingsconstructies; voeten en balken, fundatie poeren; 4.5 C Brandwerendheid hoofddraagconstructie: -; 4.7 Materiaal: beton_gewapend_ihw; 4.8 Bouwfase: Bestaand; 4.8 C Sterkteklasse: -; 4.8 C Milieuklasse: -; 4.8 C Wapeningshoeveelheid: 75,00 kg/m³

# IfcOpeningElement: Opening (14)
Pset_OpeningElementCommon - sets with these values: 2
Name | In | Classification | Reference | 3.3 Bouwlaag | 4.8 Bouwfase | 3.5 Naamgeving element
Basic Wall:22.21_WA_Beton 220mm:614068:1 | -1 kelder | 22.21 binnenwanden; constructief, massieve wanden (NL-Sfb) | 22.21_WA_Beton 220mm | -1 kelder | Bestaand | ILS Ontwerp en Engineering - 4.3 Dragend: yes
2 x beton 250mm | 00 begane grond |  | 23.21_FL_Beton170mm
2 x 31.10_Constructiesparing | 00 begane grond | 31.10 buitenwandopeningen; niet gevuld, algemeen (verzamelniveau) (NL-Sfb) | 31.10_1150x2260 | 00 begane grond | Nieuw | 31.10_Constructiesparing
2 x  | 01 eerste verdieping | 23.21 vloeren; constructief, vrijdragende vloeren (NL-Sfb) | 23.21_FL_Beton190mm (DATO) | 01 eerste verdieping | Bestaand | beton 250mm | ILS Ontwerp en Engineering - 4.3 Dragend: yes; 4.4 Uitwendig: no; 3.4 Entiteit: IfcSlab; 3.4 Entiteit type: FLOOR; 3.6 NL-SfB code: 23.21; 3.6 NL-SfB omschrijving: vloeren; constructief, vrijdragende vloeren; 4.5 C Brandwerendheid hoofddraagconstructie: 60; 4.8 C Sterkteklasse: C30/37; 4.8 C Milieuklasse: XC1; Pset_FireRatingProperties - FireResistanceRating: 60
2 x 31.10_Constructiesparing | -1 kelder | 32.10 binnenwandopeningen; niet gevuld, algemeen (verzamelniveau) (NL-Sfb) | 32.10_900x2450 | -1 kelder | Nieuw | 31.10_Constructiesparing
2 x 31.10_Constructiesparing | 00 begane grond | 32.10 binnenwandopeningen; niet gevuld, algemeen (verzamelniveau) (NL-Sfb) | 32.10_900x2450 | 00 begane grond | Nieuw | 31.10_Constructiesparing
31.10_Constructiesparing | 00 begane grond | 32.10 binnenwandopeningen; niet gevuld, algemeen (verzamelniveau) (NL-Sfb) | 32.10_900x2450 | -1 kelder | Nieuw | 31.10_Constructiesparing
31.10_Constructiesparing | 01 eerste verdieping | 32.10 binnenwandopeningen; niet gevuld, algemeen (verzamelniveau) (NL-Sfb) | 32.10_900x2450 | 00 begane grond | Nieuw | 31.10_Constructiesparing
31.10_Constructiesparing | -1 kelder | 31.10 buitenwandopeningen; niet gevuld, algemeen (verzamelniveau) (NL-Sfb) | 31.10_standaard | -1 kelder | Nieuw | 31.10_Constructiesparing

# IfcPile: Type 01 (11)
In: -1 kelder
Type - Description: Type 01; Classification: 17.21 paalfunderingen; geheid, dragende palen (NL-Sfb); Material: beton_gewapend_ihw_c30/37
Pset_ConcreteElementGeneral - StructuralClass: C30/37; EnvironmentalClass: XC2; FireRating: 0
Pset_FireRatingProperties - FireResistanceRating: 0
Pset_QuantityTakeOff - Reference: Type 01
ILS Ontwerp en Engineering - 4.3 Dragend: yes; 3.3 Bouwlaag: -1 kelder; 3.5 Naamgeving element: 17.21_Stalen buispaal; 3.5 Type: Type 01; 3.6 NL-SfB code: 17.21; 3.6 NL-SfB omschrijving: paalfunderingen; geheid, dragende palen; 4.5 B Brandwerendheid (WBDBO): 0; 4.5 C Brandwerendheid hoofddraagconstructie: 0; 4.7 Materiaal: beton_gewapend_ihw_c30/37; 4.8 Bouwfase: Nieuw; 4.8 C Sterkteklasse: C30/37; 4.8 C Milieuklasse: XC2; 4.8 C Wapeningshoeveelheid: 0,00 kg/m³

# IfcPile: Type 01 (39)
In: 00 begane grond
Type - Description: Type 01; Classification: 17.21 paalfunderingen; geheid, dragende palen (NL-Sfb); Material: beton_gewapend_prefab-element_c45/55
Pset_ConcreteElementGeneral - StructuralClass: -; EnvironmentalClass: -; FireRating: 0
ILS Ontwerp en Engineering - 4.3 Dragend: yes; 3.3 Bouwlaag: 00 begane grond; 3.5 Naamgeving element: 17.21_Prefab funderingspaal rond; 3.5 Type: Type 01; 3.6 NL-SfB code: 17.21; 3.6 NL-SfB omschrijving: paalfunderingen; geheid, dragende palen; 4.5 B Brandwerendheid (WBDBO): 0; 4.7 Materiaal: beton_gewapend_prefab-element_c45/55; 4.8 Bouwfase: Bestaand; 4.8 C Sterkteklasse: -; 4.8 C Milieuklasse: -; 4.8 C Wapeningshoeveelheid: 0,00 kg/m³
Name | FireResistanceRating = 4.5 C Brandwerendheid hoofddraagconstructie | Reference
36 x 17.21_Prefab funderingspaal rond | - | Type 05
3 x 17.21_Prefab funderingspaal rond | 0 | Type 01

# IfcSlab: 13.22_SFO_Beton1170mm (2)
In: 00 begane grond
Type - PredefinedType: BASESLAB
Type - Pset_ReinforcementBarPitchOfSlab - Description: beton 1170mm
Type - Pset_SlabCommon - ThermalTransmittance: 0.894017 kg/K/s3
Classification: 13.22 vloeren op grondslag; constructief, vloeren als gebouwonderdeel (NL-Sfb); Material: beton_gewapend_ihw
Pset_QuantityTakeOff - Reference: 13.22_SFO_Beton1170mm; sets with these values: 2
Pset_SlabCommon - LoadBearing: yes; IsExternal: no; Reference: 13.22_SFO_Beton1170mm; PitchAngle: 56.1408 deg
ILS Ontwerp en Engineering - 4.3 Dragend: yes; 3.3 Bouwlaag: 00 begane grond; 4.8 Bouwfase: Bestaand
Name (Foundation Slab:13.22_SFO_Beton1170mm:...)
671503
672479

# IfcSlab: 13.22_SFO_Beton120mm, Foundation Slab:13.22_SFO_Beton120mm:635197
In: 00 begane grond
Type - PredefinedType: BASESLAB; Material: beton_gewapend_ihw 120 mm
Type - Pset_ReinforcementBarPitchOfSlab - Description: beton 120mm
Type - Pset_SlabCommon - ThermalTransmittance: 8.71667 kg/K/s3
Classification: 13.22 vloeren op grondslag; constructief, vloeren als gebouwonderdeel (NL-Sfb)
Pset_QuantityTakeOff - Reference: 13.22_SFO_Beton120mm; sets with these values: 2
Pset_SlabCommon - LoadBearing: yes; IsExternal: no; PitchAngle: 0 deg; Reference: 13.22_SFO_Beton120mm
ILS Ontwerp en Engineering - 4.3 Dragend: yes; 3.3 Bouwlaag: 00 begane grond; 4.8 Bouwfase: Bestaand

# IfcSlab: 13.22_SFO_Beton200mm, Foundation Slab:13.22_SFO_Beton200mm:618577
In: -1 kelder
Type - PredefinedType: BASESLAB; Material: beton_gewapend_ihw 200 mm
Type - Pset_ReinforcementBarPitchOfSlab - Description: beton 200mm
Type - Pset_SlabCommon - ThermalTransmittance: 5.23 kg/K/s3
Classification: 13.22 vloeren op grondslag; constructief, vloeren als gebouwonderdeel (NL-Sfb)
Pset_QuantityTakeOff - Reference: 13.22_SFO_Beton200mm; sets with these values: 2
Pset_SlabCommon - LoadBearing: yes; IsExternal: no; Reference: 13.22_SFO_Beton200mm; PitchAngle: 0 deg
ILS Ontwerp en Engineering - 4.3 Dragend: yes; 3.3 Bouwlaag: -1 kelder; 4.8 Bouwfase: Bestaand

# IfcSlab: 13.22_SFO_Beton250mm, Foundation Slab:13.22_SFO_Beton250mm:620730
In: -1 kelder
Type - PredefinedType: BASESLAB; Material: beton_gewapend_ihw 250 mm
Type - Pset_ReinforcementBarPitchOfSlab - Description: beton 250mm
Type - Pset_SlabCommon - ThermalTransmittance: 4.184 kg/K/s3
Classification: 13.22 vloeren op grondslag; constructief, vloeren als gebouwonderdeel (NL-Sfb)
Pset_QuantityTakeOff - Reference: 13.22_SFO_Beton250mm; sets with these values: 2
Pset_SlabCommon - LoadBearing: yes; IsExternal: no; PitchAngle: 0 deg; Reference: 13.22_SFO_Beton250mm
ILS Ontwerp en Engineering - 4.3 Dragend: yes; 3.3 Bouwlaag: -1 kelder; 4.8 Bouwfase: Bestaand

# IfcSlab: 13.22_SFO_Beton250mm-C30/37 (2)
In: 00 begane grond
Type - PredefinedType: BASESLAB; Material: beton_gewapend_ihw_c30/37 250 mm
Type - Pset_ReinforcementBarPitchOfSlab - Description: beton 250mm
Type - Pset_SlabCommon - ThermalTransmittance: 4.184 kg/K/s3
Classification: 13.22 vloeren op grondslag; constructief, vloeren als gebouwonderdeel (NL-Sfb)
Pset_QuantityTakeOff - Reference: 13.22_SFO_Beton250mm-C30/37; sets with these values: 2
Pset_SlabCommon - LoadBearing: yes; IsExternal: no; PitchAngle: 0 deg; Reference: 13.22_SFO_Beton250mm-C30/37
ILS Ontwerp en Engineering - 4.3 Dragend: yes; 3.3 Bouwlaag: 00 begane grond; 4.8 Bouwfase: Nieuw
Name (Foundation Slab:13.22_SFO_Beton250mm-C30/37:...)
728975
858945

# IfcSlab: 23.21_FL_Beton190mm (DATO) (2)
In: 01 eerste verdieping
Type - PredefinedType: FLOOR; Material: beton_gewapend_ihw 190 mm
Type - Pset_ConcreteElementGeneral - StructuralClass: C30/37; EnvironmentalClass: XC1; FireRating: -
Type - Pset_FireRatingProperties - FireResistanceRating: 60
Type - Pset_ReinforcementBarPitchOfSlab - Description: best. DATO vloer
Type - Pset_SlabCommon - FireRating: -; ThermalTransmittance: 5.50526 kg/K/s3
Classification: 23.21 vloeren; constructief, vrijdragende vloeren (NL-Sfb)
Pset_QuantityTakeOff - Reference: 23.21_FL_Beton190mm (DATO); sets with these values: 2
Pset_SlabCommon - LoadBearing: yes; IsExternal: no; PitchAngle: 0 deg; Reference: 23.21_FL_Beton190mm (DATO)
ILS Ontwerp en Engineering - 4.3 Dragend: yes; 4.4 Uitwendig: no; 3.3 Bouwlaag: 01 eerste verdieping; 3.4 Entiteit: IfcSlab; 3.4 Entiteit type: FLOOR; 3.5 Naamgeving element: beton 250mm; 3.6 NL-SfB code: 23.21; 3.6 NL-SfB omschrijving: vloeren; constructief, vrijdragende vloeren; 4.5 C Brandwerendheid hoofddraagconstructie: 60; 4.8 Bouwfase: Bestaand; 4.8 C Sterkteklasse: C30/37; 4.8 C Milieuklasse: XC1

# IfcSlab: 23.21_FL_Houtenvloer190mm (3)
In: 01 eerste verdieping
Type - PredefinedType: FLOOR; Material: hout_multiplex_plaat 20 mm, hout_vuren_generiek_c18 170 mm
Type - Pset_ReinforcementBarPitchOfSlab - Description: Houtenvloer 190mm
Classification: 23.21 vloeren; constructief, vrijdragende vloeren (NL-Sfb)
Pset_QuantityTakeOff - Reference: 23.21_FL_Houtenvloer190mm; sets with these values: 2
Pset_SlabCommon - LoadBearing: yes; IsExternal: no; PitchAngle: 0 deg; Reference: 23.21_FL_Houtenvloer190mm
ILS Ontwerp en Engineering - 4.3 Dragend: yes; 3.3 Bouwlaag: 01 eerste verdieping; 4.8 Bouwfase: Nieuw
Name (Floor:23.21_FL_Houtenvloer190mm:...)
785143
785143:2
791717

# IfcSlab: 23.21_FL_Lewisvloer50-171 (4)
Type - PredefinedType: FLOOR; Material: beton_gewapend_ihw_c20/25 50 mm, hout_vuren_generiek_c24 171 mm
Type - Pset_ReinforcementBarPitchOfSlab - Description: Lewisplaatvloer
Type - Pset_SlabCommon - ThermalTransmittance: 20.92 kg/K/s3
Description: {$type("IfcDescription[Type]")}; Classification: 23.21 vloeren; constructief, vrijdragende vloeren (NL-Sfb)
Pset_ConcreteElementGeneral - StructuralClass: {$type("StructuralClass[Type]")}; EnvironmentalClass: {$type("EnvironmentalClass[Type]")}
Pset_FireRatingProperties - FireResistanceRating: {$type("FireResistanceRating[Type]")}
Pset_QuantityTakeOff - Reference: 23.21_FL_Lewisvloer50-171; sets with these values: 2
Pset_SlabCommon - LoadBearing: yes; IsExternal: no; PitchAngle: 0 deg; Reference: 23.21_FL_Lewisvloer50-171
ILS Ontwerp en Engineering - 4.3 Dragend: yes; 4.4 Uitwendig: no; 3.4 Entiteit: IfcSlab; 3.4 Entiteit type: FLOOR; 3.5 Naamgeving element: beton 250mm; 3.5 Type: {$type("IfcDescription[Type]")}; 3.6 NL-SfB code: 23.21; 3.6 NL-SfB omschrijving: vloeren; constructief, vrijdragende vloeren; 4.5 C Brandwerendheid hoofddraagconstructie: {$type("FireResistanceRating[Type]")}; 4.8 Bouwfase: Nieuw; 4.8 C Sterkteklasse: {$type("StructuralClass[Type]")}; 4.8 C Milieuklasse: {$type("EnvironmentalClass[Type]")}
Name | In | 3.3 Bouwlaag
2 x beton 250mm | -1 kelder | -1 kelder
2 x beton 250mm | 00 begane grond | 00 begane grond

# IfcSlab: 23.21_FL_Lewisvloer50-220, Floor:23.21_FL_Lewisvloer50-220:731229
In: 01 eerste verdieping
Type - PredefinedType: FLOOR; Material: beton_gewapend_ihw_c20/25 50 mm, hout_vuren_generiek_c24 220 mm
Type - Pset_ReinforcementBarPitchOfSlab - Description: Lewisplaatvloer
Type - Pset_SlabCommon - ThermalTransmittance: 20.92 kg/K/s3
Classification: 23.21 vloeren; constructief, vrijdragende vloeren (NL-Sfb)
Pset_QuantityTakeOff - Reference: 23.21_FL_Lewisvloer50-220; sets with these values: 2
Pset_SlabCommon - IsExternal: no; PitchAngle: 0 deg; Reference: 23.21_FL_Lewisvloer50-220; LoadBearing: no
ILS Ontwerp en Engineering - 3.3 Bouwlaag: 01 eerste verdieping; 3.4 Entiteit: IfcSlab; 3.4 Entiteit type: FLOOR; 4.3 Dragend: no; 4.8 Bouwfase: Nieuw

# IfcSlab: 23.21_FL_best.Houtenvloer190mm (2)
In: 01 eerste verdieping
Type - PredefinedType: FLOOR; Material: hout_multiplex_plaat 20 mm, hout_vuren_generiek_c18 170 mm
Type - Pset_ReinforcementBarPitchOfSlab - Description: Houtenvloer 190mm
Classification: 23.21 vloeren; constructief, vrijdragende vloeren (NL-Sfb)
Pset_QuantityTakeOff - Reference: 23.21_FL_best.Houtenvloer190mm; sets with these values: 2
Pset_SlabCommon - LoadBearing: yes; IsExternal: no; PitchAngle: 0 deg; Reference: 23.21_FL_best.Houtenvloer190mm
ILS Ontwerp en Engineering - 4.3 Dragend: yes; 3.3 Bouwlaag: 01 eerste verdieping; 4.8 Bouwfase: Bestaand
Name (Floor:23.21_FL_best.Houtenvloer190mm:...)
708535
731407

# IfcSlab: 23.21_vloer (2)
In: 00 begane grond
Type - Description: ihwg beton vloer 200mm; PredefinedType: FLOOR; Material: beton_gewapend_ihw_c30/37 150 mm
Type - Pset_ConcreteElementGeneral - StructuralClass: C30/37; EnvironmentalClass: XC1; FireRating: -
Type - Pset_FireRatingProperties - FireResistanceRating: 60
Type - Pset_ReinforcementBarPitchOfSlab - Description: beton 150mm
Type - Pset_SlabCommon - FireRating: -; ThermalTransmittance: 6.97333 kg/K/s3
Classification: 23.21 vloeren; constructief, vrijdragende vloeren (NL-Sfb)
Pset_QuantityTakeOff - Reference: 23.21_FL_Beton150mm-C30/37; sets with these values: 2
Pset_SlabCommon - LoadBearing: yes; IsExternal: no; PitchAngle: 0 deg; Reference: 23.21_FL_Beton150mm-C30/37
ILS Ontwerp en Engineering - 4.3 Dragend: yes; 4.4 Uitwendig: no; 3.3 Bouwlaag: 00 begane grond; 3.4 Entiteit: IfcSlab; 3.4 Entiteit type: FLOOR; 3.5 Naamgeving element: beton 250mm; 3.5 Type: ihwg beton vloer 200mm; 3.6 NL-SfB code: 23.21; 3.6 NL-SfB omschrijving: vloeren; constructief, vrijdragende vloeren; 4.5 C Brandwerendheid hoofddraagconstructie: 60; 4.8 Bouwfase: Nieuw; 4.8 C Sterkteklasse: C30/37; 4.8 C Milieuklasse: XC1

# IfcSlab: 23.21_vloer (2)
Type - Description: ihwg beton vloer 200mm; PredefinedType: FLOOR; Material: beton_gewapend_ihw_c30/37 200 mm
Type - Pset_ConcreteElementGeneral - StructuralClass: C30/37; EnvironmentalClass: XC1; FireRating: -
Type - Pset_FireRatingProperties - FireResistanceRating: 60
Type - Pset_ReinforcementBarPitchOfSlab - Description: beton 200mm
Type - Pset_SlabCommon - FireRating: -; ThermalTransmittance: 5.23 kg/K/s3
Classification: 23.21 vloeren; constructief, vrijdragende vloeren (NL-Sfb)
Pset_QuantityTakeOff - Reference: 23.21_FL_Beton200mm-C30/37; sets with these values: 2
Pset_SlabCommon - LoadBearing: yes; IsExternal: no; PitchAngle: 0 deg; Reference: 23.21_FL_Beton200mm-C30/37
ILS Ontwerp en Engineering - 4.3 Dragend: yes; 4.4 Uitwendig: no; 3.4 Entiteit: IfcSlab; 3.4 Entiteit type: FLOOR; 3.5 Naamgeving element: beton 250mm; 3.5 Type: ihwg beton vloer 200mm; 3.6 NL-SfB code: 23.21; 3.6 NL-SfB omschrijving: vloeren; constructief, vrijdragende vloeren; 4.5 C Brandwerendheid hoofddraagconstructie: 60; 4.8 Bouwfase: Nieuw; 4.8 C Sterkteklasse: C30/37; 4.8 C Milieuklasse: XC1
Name | In | 3.3 Bouwlaag
beton 250mm | 00 begane grond | 00 begane grond
beton 250mm | -1 kelder | -1 kelder

# IfcSlab: 23.21_vloer, beton 250mm
In: 00 begane grond
Type - Description: ihwg beton vloer 250mm; PredefinedType: FLOOR; Material: beton_gewapend_ihw 150 mm
Type - Pset_ConcreteElementGeneral - StructuralClass: C30/37; EnvironmentalClass: XC1; FireRating: -
Type - Pset_FireRatingProperties - FireResistanceRating: 60
Type - Pset_ReinforcementBarPitchOfSlab - Description: beton 250mm
Type - Pset_SlabCommon - FireRating: -; ThermalTransmittance: 6.97333 kg/K/s3
Classification: 23.21 vloeren; constructief, vrijdragende vloeren (NL-Sfb)
Pset_QuantityTakeOff - Reference: 23.21_FL_Beton150mm; sets with these values: 2
Pset_SlabCommon - LoadBearing: yes; IsExternal: no; PitchAngle: 0 deg; Reference: 23.21_FL_Beton150mm
ILS Ontwerp en Engineering - 4.3 Dragend: yes; 4.4 Uitwendig: no; 3.3 Bouwlaag: 00 begane grond; 3.4 Entiteit: IfcSlab; 3.4 Entiteit type: FLOOR; 3.5 Naamgeving element: beton 250mm; 3.5 Type: ihwg beton vloer 250mm; 3.6 NL-SfB code: 23.21; 3.6 NL-SfB omschrijving: vloeren; constructief, vrijdragende vloeren; 4.5 C Brandwerendheid hoofddraagconstructie: 60; 4.8 Bouwfase: Bestaand; 4.8 C Sterkteklasse: C30/37; 4.8 C Milieuklasse: XC1

# IfcSlab: 23.21_vloer (2)
In: 00 begane grond
Type - Description: ihwg beton vloer 250mm; PredefinedType: FLOOR; Material: beton_gewapend_ihw 170 mm
Type - Pset_ConcreteElementGeneral - StructuralClass: C30/37; EnvironmentalClass: XC1; FireRating: -
Type - Pset_FireRatingProperties - FireResistanceRating: 60
Type - Pset_ReinforcementBarPitchOfSlab - Description: beton 170mm
Type - Pset_SlabCommon - FireRating: -; ThermalTransmittance: 6.15294 kg/K/s3
Classification: 23.21 vloeren; constructief, vrijdragende vloeren (NL-Sfb)
Pset_QuantityTakeOff - Reference: 23.21_FL_Beton170mm; sets with these values: 2
Pset_SlabCommon - LoadBearing: yes; IsExternal: no; PitchAngle: 0 deg; Reference: 23.21_FL_Beton170mm
ILS Ontwerp en Engineering - 4.3 Dragend: yes; 3.3 Bouwlaag: 00 begane grond; 3.4 Entiteit: IfcSlab; 3.4 Entiteit type: FLOOR; 3.5 Naamgeving element: beton 250mm; 3.5 Type: ihwg beton vloer 250mm; 3.6 NL-SfB code: 23.21; 3.6 NL-SfB omschrijving: vloeren; constructief, vrijdragende vloeren; 4.4 Uitwendig: no; 4.5 C Brandwerendheid hoofddraagconstructie: 60; 4.8 Bouwfase: Bestaand; 4.8 C Sterkteklasse: C30/37; 4.8 C Milieuklasse: XC1

# IfcSlab: 23.21_vloer (2)
In: 00 begane grond
Type - Description: ihwg beton vloer 250mm; PredefinedType: FLOOR; Material: beton_gewapend_ihw_c30/37 170 mm
Type - Pset_ConcreteElementGeneral - StructuralClass: C30/37; EnvironmentalClass: XC1; FireRating: -
Type - Pset_FireRatingProperties - FireResistanceRating: 60
Type - Pset_ReinforcementBarPitchOfSlab - Description: beton 170mm
Type - Pset_SlabCommon - FireRating: -; ThermalTransmittance: 6.15294 kg/K/s3
Classification: 23.21 vloeren; constructief, vrijdragende vloeren (NL-Sfb)
Pset_QuantityTakeOff - Reference: 23.21_FL_Beton170mm - C30/37; sets with these values: 2
Pset_SlabCommon - LoadBearing: yes; IsExternal: no; PitchAngle: 0 deg; Reference: 23.21_FL_Beton170mm - C30/37
ILS Ontwerp en Engineering - 4.3 Dragend: yes; 4.4 Uitwendig: no; 3.3 Bouwlaag: 00 begane grond; 3.4 Entiteit: IfcSlab; 3.4 Entiteit type: FLOOR; 3.5 Naamgeving element: beton 250mm; 3.5 Type: ihwg beton vloer 250mm; 3.6 NL-SfB code: 23.21; 3.6 NL-SfB omschrijving: vloeren; constructief, vrijdragende vloeren; 4.5 C Brandwerendheid hoofddraagconstructie: 60; 4.8 Bouwfase: Nieuw; 4.8 C Sterkteklasse: C30/37; 4.8 C Milieuklasse: XC1

# IfcWall: 22.21_muur (6)
In: -1 kelder
Type - Description: dragende betonnen muur; PredefinedType: STANDARD; Material: beton_gewapend_ihw 220 mm
Type - Pset_ConcreteElementGeneral - FireRating: 0
Type - Pset_ReinforcementBarPitchOfWall - Description: beton 220mm
Type - Pset_WallCommon - FireRating: 0; ThermalTransmittance: 4.75455 kg/K/s3
Classification: 22.21 binnenwanden; constructief, massieve wanden (NL-Sfb)
Pset_QuantityTakeOff - sets with these values: 2
Pset_WallCommon - IsExternal: yes; ExtendToStructure: no; LoadBearing: yes
ILS Ontwerp en Engineering - 3.3 Bouwlaag: -1 kelder; 4.3 Dragend: yes; 4.8 Bouwfase: Bestaand
Name (Basic Wall:...) | Pset_QuantityTakeOff, Reference = Pset_WallCommon, Reference
22.21_WA_Beton 220mm:614009 | 22.21_WA_Beton 220mm
22.21_WA_Beton 220mm:614414 | 22.21_WA_Beton 220mm
22.21_WA_Beton 220mm:615985 | 22.21_WA_Beton 220mm
22.21_WA_Beton 220mm:616295 | 22.21_WA_Beton 220mm
22.21_WA_Beton 220mm:616349 | 22.21_WA_Beton 220mm
22.21_WA_Beton var:618774 | 22.21_WA_Beton var

# IfcWall: 22.21_muur (2)
In: 00 begane grond
Type - Description: dragende metselwerk muur; PredefinedType: STANDARD; Material: steenachtig_baksteen_steen 220 mm
Type - Pset_ConcreteElementGeneral - FireRating: 0
Type - Pset_ReinforcementBarPitchOfWall - Description: metselwerk 220mm
Type - Pset_WallCommon - FireRating: 0
Classification: 22.21 binnenwanden; constructief, massieve wanden (NL-Sfb)
Pset_QuantityTakeOff - Reference: 22.21_WA_Metselwerk 220mm; sets with these values: 2
Pset_WallCommon - LoadBearing: yes; IsExternal: no; Reference: 22.21_WA_Metselwerk 220mm
ILS Ontwerp en Engineering - 4.3 Dragend: yes; 3.3 Bouwlaag: 00 begane grond; 4.8 Bouwfase: Bestaand
Name (Basic Wall:22.21_WA_Metselwerk 220mm:...) | ExtendToStructure
690630 | yes
725725 | no

# IfcWall: 22.21_muur, Basic Wall:22.21_WA_Metselwerk 660mm:724926
In: 00 begane grond
Type - Description: dragende metselwerk muur; PredefinedType: STANDARD; Material: steenachtig_baksteen_steen 660 mm
Type - Pset_ConcreteElementGeneral - FireRating: 0
Type - Pset_ReinforcementBarPitchOfWall - Description: metselwerk 660mm
Type - Pset_WallCommon - FireRating: 0
Classification: 22.21 binnenwanden; constructief, massieve wanden (NL-Sfb)
Pset_QuantityTakeOff - Reference: 22.21_WA_Metselwerk 660mm; sets with these values: 2
Pset_WallCommon - ExtendToStructure: no; LoadBearing: yes; IsExternal: no; Reference: 22.21_WA_Metselwerk 660mm
ILS Ontwerp en Engineering - 4.3 Dragend: yes; 3.3 Bouwlaag: 00 begane grond; 4.8 Bouwfase: Bestaand

# IfcWall: NLRS_22_WA_LIB_Muur_gen_EPA:Kalkzandsteen 200mm, Basic Wall:22.21_WA_Kalkzandsteen150mm:836278
In: -1 kelder
Type - PredefinedType: STANDARD; Material: steenachtig_kalkzandsteen_generiek 150 mm
Type - Pset_ReinforcementBarPitchOfWall - Description: kalkzandsteen 150mm
Classification: 22.21 binnenwanden; constructief, massieve wanden (NL-Sfb)
Pset_QuantityTakeOff - Reference: 22.21_WA_Kalkzandsteen150mm; sets with these values: 2
Pset_WallCommon - ExtendToStructure: no; LoadBearing: yes; IsExternal: no; Reference: 22.21_WA_Kalkzandsteen150mm
ILS Ontwerp en Engineering - 4.3 Dragend: yes; 3.3 Bouwlaag: -1 kelder; 4.8 Bouwfase: Nieuw

# IfcWallStandardCase: 22.21_muur (16)
Type - Description: dragende betonnen muur; PredefinedType: STANDARD; Material: beton_gewapend_ihw 220 mm
Type - Pset_ConcreteElementGeneral - FireRating: 0
Type - Pset_ReinforcementBarPitchOfWall - Description: beton 220mm
Type - Pset_WallCommon - FireRating: 0; ThermalTransmittance: 4.75455 kg/K/s3
Classification: 22.21 binnenwanden; constructief, massieve wanden (NL-Sfb)
Pset_QuantityTakeOff - Reference: 22.21_WA_Beton 220mm; sets with these values: 2
Pset_WallCommon - Reference: 22.21_WA_Beton 220mm; IsExternal: yes; ExtendToStructure: no; LoadBearing: yes
ILS Ontwerp en Engineering - 4.3 Dragend: yes; 4.8 Bouwfase: Bestaand
Name (Basic Wall:22.21_WA_Beton 220mm:...) | In | 3.3 Bouwlaag
614068 | -1 kelder | -1 kelder
614245 | -1 kelder | -1 kelder
614583 | -1 kelder | -1 kelder
614760 | -1 kelder | -1 kelder
614909 | -1 kelder | -1 kelder
615085 | -1 kelder | -1 kelder
615261 | -1 kelder | -1 kelder
615414 | -1 kelder | -1 kelder
615493 | -1 kelder | -1 kelder
615617 | -1 kelder | -1 kelder
615708 | -1 kelder | -1 kelder
615846 | -1 kelder | -1 kelder
616106 | -1 kelder | -1 kelder
620604 | -1 kelder | -1 kelder
634759 | 00 begane grond | 00 begane grond
634844 | 00 begane grond | 00 begane grond

# IfcWallStandardCase: 22.21_muur (3)
In: 00 begane grond
Type - Description: dragende betonnen muur; PredefinedType: STANDARD; Material: beton_gewapend_ihw_c30/37 200 mm
Type - Pset_ConcreteElementGeneral - FireRating: 0
Type - Pset_ReinforcementBarPitchOfWall - Description: beton 200mm
Type - Pset_WallCommon - FireRating: 0; ThermalTransmittance: 5.23 kg/K/s3
Classification: 22.21 binnenwanden; constructief, massieve wanden (NL-Sfb)
Pset_QuantityTakeOff - Reference: 22.21_WA_Beton 200mm - C30/37; sets with these values: 2
Pset_WallCommon - IsExternal: yes; ExtendToStructure: no; LoadBearing: yes; Reference: 22.21_WA_Beton 200mm - C30/37
ILS Ontwerp en Engineering - 4.3 Dragend: yes; 3.3 Bouwlaag: 00 begane grond; 4.8 Bouwfase: Nieuw
Name (Basic Wall:22.21_WA_Beton 200mm - C30/37:...)
728061
728130
728204

# IfcWallStandardCase: 22.21_muur (4)
In: -1 kelder
Type - Description: dragende betonnen muur; PredefinedType: STANDARD; Material: beton_gewapend_ihw_c30/37 220 mm
Type - Pset_ConcreteElementGeneral - FireRating: 0
Type - Pset_ReinforcementBarPitchOfWall - Description: beton 220mm
Type - Pset_WallCommon - FireRating: 0; ThermalTransmittance: 4.75455 kg/K/s3
Classification: 22.21 binnenwanden; constructief, massieve wanden (NL-Sfb)
Pset_QuantityTakeOff - Reference: 22.21_WA_Beton 220mm - C30/37; sets with these values: 2
Pset_WallCommon - IsExternal: yes; ExtendToStructure: no; LoadBearing: yes; Reference: 22.21_WA_Beton 220mm - C30/37
ILS Ontwerp en Engineering - 4.3 Dragend: yes; 3.3 Bouwlaag: -1 kelder; 4.8 Bouwfase: Nieuw
Name (Basic Wall:22.21_WA_Beton 220mm - C30/37:...)
783468
783526
783594
783656

# IfcWallStandardCase: 22.21_muur (19)
In: 00 begane grond
Type - Description: dragende metselwerk muur; PredefinedType: STANDARD; Material: steenachtig_baksteen_steen 220 mm
Type - Pset_ConcreteElementGeneral - FireRating: 0
Type - Pset_ReinforcementBarPitchOfWall - Description: metselwerk 220mm
Type - Pset_WallCommon - FireRating: 0
Classification: 22.21 binnenwanden; constructief, massieve wanden (NL-Sfb)
Pset_QuantityTakeOff - Reference: 22.21_WA_Metselwerk 220mm; sets with these values: 2
Pset_WallCommon - LoadBearing: yes; IsExternal: no; Reference: 22.21_WA_Metselwerk 220mm
ILS Ontwerp en Engineering - 4.3 Dragend: yes; 3.3 Bouwlaag: 00 begane grond; 4.8 Bouwfase: Bestaand
Name (Basic Wall:22.21_WA_Metselwerk 220mm:...) | ExtendToStructure
684681 | no
687798 | yes
688321 | yes
689178 | yes
689300 | yes
690133 | yes
690957 | yes
690965 | yes
691760 | yes
691807 | yes
691820 | yes
691829 | yes
692014 | yes
692170 | yes
692226 | yes
706550 | no
706687 | no
724402 | no
724519 | no

# IfcWallStandardCase: NLRS_21_WA_LIB_Wand_gen_EPA:HSB-wand 130mm (3)
Type - PredefinedType: STANDARD; Material: hout_multiplex_plaat 15 mm, isolatie_steenwol_deken 100 mm, hout_multiplex_plaat 15 mm
Type - Pset_ReinforcementBarPitchOfWall - Description: HSB-wand 130mm
Type - Pset_WallCommon - ThermalTransmittance: 0.34 kg/K/s3
Classification: 21.23 buitenwanden; constructief, systeemwanden (NL-Sfb)
Pset_QuantityTakeOff - Reference: 21.23_WA_HSB-Wand130mm; sets with these values: 2
Pset_WallCommon - IsExternal: yes; LoadBearing: yes; Reference: 21.23_WA_HSB-Wand130mm
ILS Ontwerp en Engineering - 4.3 Dragend: yes; 4.8 Bouwfase: Nieuw
Name (Basic Wall:21.23_WA_HSB-Wand130mm:...) | In | ExtendToStructure | 3.3 Bouwlaag
792431 | 00 begane grond | yes | 00 begane grond
792570 | 00 begane grond | no | 00 begane grond
792990 | 01 eerste verdieping | no | 01 eerste verdieping

# IfcWallStandardCase: NLRS_22_WA_LIB_Muur_gen_EPA:Kalkzandsteen 200mm (10)
Type - PredefinedType: STANDARD; Material: steenachtig_kalkzandsteen_generiek 150 mm
Type - Pset_ReinforcementBarPitchOfWall - Description: kalkzandsteen 150mm
Classification: 22.21 binnenwanden; constructief, massieve wanden (NL-Sfb)
Pset_QuantityTakeOff - Reference: 22.21_WA_Kalkzandsteen150mm; sets with these values: 2
Pset_WallCommon - ExtendToStructure: no; IsExternal: no; Reference: 22.21_WA_Kalkzandsteen150mm
ILS Ontwerp en Engineering - 4.8 Bouwfase: Nieuw
Name (Basic Wall:22.21_WA_Kalkzandsteen150mm:...) | In | LoadBearing = 4.3 Dragend | 3.3 Bouwlaag
836209 | -1 kelder | yes | -1 kelder
836389 | -1 kelder | yes | -1 kelder
839735 | -1 kelder | yes | -1 kelder
839899 | -1 kelder | no | -1 kelder
839928 | -1 kelder | no | -1 kelder
840394 | -1 kelder | no | -1 kelder
916199 | -1 kelder | yes | -1 kelder
921629 | 00 begane grond | no | 00 begane grond
921630 | 00 begane grond | no | 00 begane grond
921631 | 00 begane grond | no | 00 begane grond

# IfcWallStandardCase: NLRS_22_WA_LIB_Muur_gen_EPA:Kalkzandsteen 200mm (20)
Type - PredefinedType: STANDARD; Material: steenachtig_kalkzandsteen_generiek 214 mm
Type - Pset_ReinforcementBarPitchOfWall - Description: kalkzandsteen 214mm
Classification: 22.21 binnenwanden; constructief, massieve wanden (NL-Sfb)
Pset_QuantityTakeOff - Reference: 22.21_WA_Kalkzandsteen214mm; sets with these values: 2
Pset_WallCommon - ExtendToStructure: no; LoadBearing: yes; IsExternal: no; Reference: 22.21_WA_Kalkzandsteen214mm
ILS Ontwerp en Engineering - 4.3 Dragend: yes; 4.8 Bouwfase: Nieuw
Name (Basic Wall:22.21_WA_Kalkzandsteen214mm:...) | In | 3.3 Bouwlaag
783956 | -1 kelder | -1 kelder
783957 | -1 kelder | -1 kelder
783958 | -1 kelder | -1 kelder
783959 | -1 kelder | -1 kelder
784020 | 00 begane grond | 00 begane grond
784020 | 01 eerste verdieping | 00 begane grond
784021 | 00 begane grond | 00 begane grond
784021 | 01 eerste verdieping | 00 begane grond
784022 | 00 begane grond | 00 begane grond
784022 | 01 eerste verdieping | 00 begane grond
784023 | 00 begane grond | 00 begane grond
784023 | 01 eerste verdieping | 00 begane grond
859122 | 00 begane grond | 00 begane grond
859122 | 01 eerste verdieping | 00 begane grond
859177 | 00 begane grond | 00 begane grond
859177 | 01 eerste verdieping | 00 begane grond
859240 | 00 begane grond | 00 begane grond
859240 | 01 eerste verdieping | 00 begane grond
859289 | 00 begane grond | 00 begane grond
859289 | 01 eerste verdieping | 00 begane grond
